VERSION 5.8 ;
BUSBITCHARS "[]" ;
DIVIDERCHAR "/" ;
UNITS
    DATABASE MICRONS 1000 ;
END UNITS

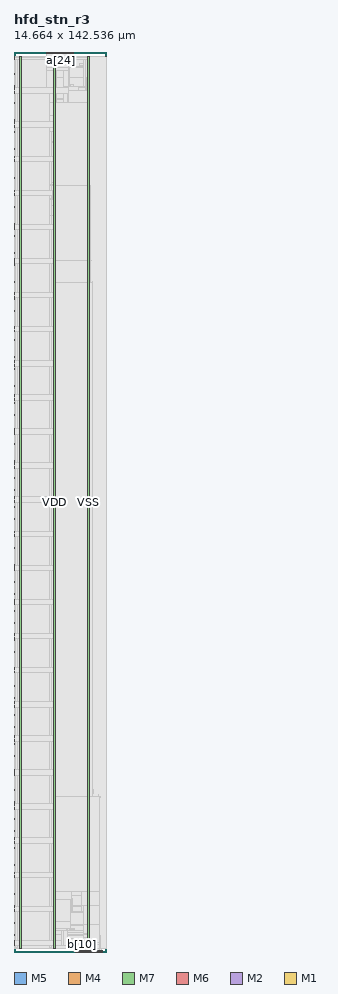
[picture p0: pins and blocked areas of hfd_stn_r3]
MACRO hfd_stn_r3
  FOREIGN hfd_stn_r3 0 0 ;
  CLASS BLOCK ;
  SIZE 14.664 BY 142.536 ;
  PIN a[0]
    DIRECTION INPUT ;
    USE SIGNAL ;
    PORT
      LAYER M5 ;
        RECT  5.184 142.344 5.208 142.536 ;
    END
  END a[0]
  PIN a[10]
    DIRECTION INPUT ;
    USE SIGNAL ;
    PORT
      LAYER M5 ;
        RECT  6.144 142.344 6.168 142.536 ;
    END
  END a[10]
  PIN a[11]
    DIRECTION INPUT ;
    USE SIGNAL ;
    PORT
      LAYER M5 ;
        RECT  6.24 142.344 6.264 142.536 ;
    END
  END a[11]
  PIN a[12]
    DIRECTION INPUT ;
    USE SIGNAL ;
    PORT
      LAYER M5 ;
        RECT  6.336 142.344 6.36 142.536 ;
    END
  END a[12]
  PIN a[13]
    DIRECTION INPUT ;
    USE SIGNAL ;
    PORT
      LAYER M5 ;
        RECT  6.432 142.344 6.456 142.536 ;
    END
  END a[13]
  PIN a[14]
    DIRECTION INPUT ;
    USE SIGNAL ;
    PORT
      LAYER M5 ;
        RECT  6.528 142.344 6.552 142.536 ;
    END
  END a[14]
  PIN a[15]
    DIRECTION INPUT ;
    USE SIGNAL ;
    PORT
      LAYER M5 ;
        RECT  6.624 142.344 6.648 142.536 ;
    END
  END a[15]
  PIN a[16]
    DIRECTION INPUT ;
    USE SIGNAL ;
    PORT
      LAYER M5 ;
        RECT  6.72 142.344 6.744 142.536 ;
    END
  END a[16]
  PIN a[17]
    DIRECTION INPUT ;
    USE SIGNAL ;
    PORT
      LAYER M5 ;
        RECT  6.816 142.344 6.84 142.536 ;
    END
  END a[17]
  PIN a[18]
    DIRECTION INPUT ;
    USE SIGNAL ;
    PORT
      LAYER M5 ;
        RECT  6.912 142.344 6.936 142.536 ;
    END
  END a[18]
  PIN a[19]
    DIRECTION INPUT ;
    USE SIGNAL ;
    PORT
      LAYER M5 ;
        RECT  7.008 142.344 7.032 142.536 ;
    END
  END a[19]
  PIN a[1]
    DIRECTION INPUT ;
    USE SIGNAL ;
    PORT
      LAYER M5 ;
        RECT  5.28 142.344 5.304 142.536 ;
    END
  END a[1]
  PIN a[20]
    DIRECTION INPUT ;
    USE SIGNAL ;
    PORT
      LAYER M5 ;
        RECT  7.104 142.344 7.128 142.536 ;
    END
  END a[20]
  PIN a[21]
    DIRECTION INPUT ;
    USE SIGNAL ;
    PORT
      LAYER M5 ;
        RECT  7.2 142.344 7.224 142.536 ;
    END
  END a[21]
  PIN a[22]
    DIRECTION INPUT ;
    USE SIGNAL ;
    PORT
      LAYER M5 ;
        RECT  7.296 142.344 7.32 142.536 ;
    END
  END a[22]
  PIN a[23]
    DIRECTION INPUT ;
    USE SIGNAL ;
    PORT
      LAYER M5 ;
        RECT  7.392 142.344 7.416 142.536 ;
    END
  END a[23]
  PIN a[24]
    DIRECTION INPUT ;
    USE SIGNAL ;
    PORT
      LAYER M5 ;
        RECT  7.488 142.344 7.512 142.536 ;
    END
  END a[24]
  PIN a[25]
    DIRECTION INPUT ;
    USE SIGNAL ;
    PORT
      LAYER M5 ;
        RECT  7.584 142.344 7.608 142.536 ;
    END
  END a[25]
  PIN a[26]
    DIRECTION INPUT ;
    USE SIGNAL ;
    PORT
      LAYER M5 ;
        RECT  7.68 142.344 7.704 142.536 ;
    END
  END a[26]
  PIN a[27]
    DIRECTION INPUT ;
    USE SIGNAL ;
    PORT
      LAYER M5 ;
        RECT  7.776 142.344 7.8 142.536 ;
    END
  END a[27]
  PIN a[28]
    DIRECTION INPUT ;
    USE SIGNAL ;
    PORT
      LAYER M5 ;
        RECT  7.872 142.344 7.896 142.536 ;
    END
  END a[28]
  PIN a[29]
    DIRECTION INPUT ;
    USE SIGNAL ;
    PORT
      LAYER M5 ;
        RECT  7.968 142.344 7.992 142.536 ;
    END
  END a[29]
  PIN a[2]
    DIRECTION INPUT ;
    USE SIGNAL ;
    PORT
      LAYER M5 ;
        RECT  5.376 142.344 5.4 142.536 ;
    END
  END a[2]
  PIN a[30]
    DIRECTION INPUT ;
    USE SIGNAL ;
    PORT
      LAYER M5 ;
        RECT  8.064 142.344 8.088 142.536 ;
    END
  END a[30]
  PIN a[31]
    DIRECTION INPUT ;
    USE SIGNAL ;
    PORT
      LAYER M5 ;
        RECT  8.16 142.344 8.184 142.536 ;
    END
  END a[31]
  PIN a[32]
    DIRECTION INPUT ;
    USE SIGNAL ;
    PORT
      LAYER M5 ;
        RECT  8.256 142.344 8.28 142.536 ;
    END
  END a[32]
  PIN a[33]
    DIRECTION INPUT ;
    USE SIGNAL ;
    PORT
      LAYER M5 ;
        RECT  8.352 142.344 8.376 142.536 ;
    END
  END a[33]
  PIN a[34]
    DIRECTION INPUT ;
    USE SIGNAL ;
    PORT
      LAYER M5 ;
        RECT  8.448 142.344 8.472 142.536 ;
    END
  END a[34]
  PIN a[35]
    DIRECTION INPUT ;
    USE SIGNAL ;
    PORT
      LAYER M5 ;
        RECT  8.544 142.344 8.568 142.536 ;
    END
  END a[35]
  PIN a[36]
    DIRECTION INPUT ;
    USE SIGNAL ;
    PORT
      LAYER M5 ;
        RECT  8.64 142.344 8.664 142.536 ;
    END
  END a[36]
  PIN a[37]
    DIRECTION INPUT ;
    USE SIGNAL ;
    PORT
      LAYER M5 ;
        RECT  8.736 142.344 8.76 142.536 ;
    END
  END a[37]
  PIN a[38]
    DIRECTION INPUT ;
    USE SIGNAL ;
    PORT
      LAYER M5 ;
        RECT  8.832 142.344 8.856 142.536 ;
    END
  END a[38]
  PIN a[39]
    DIRECTION INPUT ;
    USE SIGNAL ;
    PORT
      LAYER M5 ;
        RECT  8.928 142.344 8.952 142.536 ;
    END
  END a[39]
  PIN a[3]
    DIRECTION INPUT ;
    USE SIGNAL ;
    PORT
      LAYER M5 ;
        RECT  5.472 142.344 5.496 142.536 ;
    END
  END a[3]
  PIN a[40]
    DIRECTION INPUT ;
    USE SIGNAL ;
    PORT
      LAYER M5 ;
        RECT  9.024 142.344 9.048 142.536 ;
    END
  END a[40]
  PIN a[41]
    DIRECTION INPUT ;
    USE SIGNAL ;
    PORT
      LAYER M5 ;
        RECT  9.12 142.344 9.144 142.536 ;
    END
  END a[41]
  PIN a[42]
    DIRECTION INPUT ;
    USE SIGNAL ;
    PORT
      LAYER M5 ;
        RECT  9.216 142.344 9.24 142.536 ;
    END
  END a[42]
  PIN a[43]
    DIRECTION INPUT ;
    USE SIGNAL ;
    PORT
      LAYER M5 ;
        RECT  9.312 142.344 9.336 142.536 ;
    END
  END a[43]
  PIN a[44]
    DIRECTION INPUT ;
    USE SIGNAL ;
    PORT
      LAYER M5 ;
        RECT  9.408 142.344 9.432 142.536 ;
    END
  END a[44]
  PIN a[4]
    DIRECTION INPUT ;
    USE SIGNAL ;
    PORT
      LAYER M5 ;
        RECT  5.568 142.344 5.592 142.536 ;
    END
  END a[4]
  PIN a[5]
    DIRECTION INPUT ;
    USE SIGNAL ;
    PORT
      LAYER M5 ;
        RECT  5.664 142.344 5.688 142.536 ;
    END
  END a[5]
  PIN a[6]
    DIRECTION INPUT ;
    USE SIGNAL ;
    PORT
      LAYER M5 ;
        RECT  5.76 142.344 5.784 142.536 ;
    END
  END a[6]
  PIN a[7]
    DIRECTION INPUT ;
    USE SIGNAL ;
    PORT
      LAYER M5 ;
        RECT  5.856 142.344 5.88 142.536 ;
    END
  END a[7]
  PIN a[8]
    DIRECTION INPUT ;
    USE SIGNAL ;
    PORT
      LAYER M5 ;
        RECT  5.952 142.344 5.976 142.536 ;
    END
  END a[8]
  PIN a[9]
    DIRECTION INPUT ;
    USE SIGNAL ;
    PORT
      LAYER M5 ;
        RECT  6.048 142.344 6.072 142.536 ;
    END
  END a[9]
  PIN b[0]
    DIRECTION OUTPUT ;
    USE SIGNAL ;
    PORT
      LAYER M5 ;
        RECT  9.744 0 9.768 0.192 ;
    END
  END b[0]
  PIN b[10]
    DIRECTION OUTPUT ;
    USE SIGNAL ;
    PORT
      LAYER M5 ;
        RECT  10.704 0 10.728 0.192 ;
    END
  END b[10]
  PIN b[11]
    DIRECTION OUTPUT ;
    USE SIGNAL ;
    PORT
      LAYER M5 ;
        RECT  10.8 0 10.824 0.192 ;
    END
  END b[11]
  PIN b[12]
    DIRECTION OUTPUT ;
    USE SIGNAL ;
    PORT
      LAYER M5 ;
        RECT  10.896 0 10.92 0.192 ;
    END
  END b[12]
  PIN b[13]
    DIRECTION OUTPUT ;
    USE SIGNAL ;
    PORT
      LAYER M5 ;
        RECT  10.992 0 11.016 0.192 ;
    END
  END b[13]
  PIN b[14]
    DIRECTION OUTPUT ;
    USE SIGNAL ;
    PORT
      LAYER M5 ;
        RECT  11.088 0 11.112 0.192 ;
    END
  END b[14]
  PIN b[15]
    DIRECTION OUTPUT ;
    USE SIGNAL ;
    PORT
      LAYER M5 ;
        RECT  11.184 0 11.208 0.192 ;
    END
  END b[15]
  PIN b[16]
    DIRECTION OUTPUT ;
    USE SIGNAL ;
    PORT
      LAYER M5 ;
        RECT  11.28 0 11.304 0.192 ;
    END
  END b[16]
  PIN b[17]
    DIRECTION OUTPUT ;
    USE SIGNAL ;
    PORT
      LAYER M5 ;
        RECT  11.376 0 11.4 0.192 ;
    END
  END b[17]
  PIN b[18]
    DIRECTION OUTPUT ;
    USE SIGNAL ;
    PORT
      LAYER M5 ;
        RECT  11.472 0 11.496 0.192 ;
    END
  END b[18]
  PIN b[19]
    DIRECTION OUTPUT ;
    USE SIGNAL ;
    PORT
      LAYER M5 ;
        RECT  11.568 0 11.592 0.192 ;
    END
  END b[19]
  PIN b[1]
    DIRECTION OUTPUT ;
    USE SIGNAL ;
    PORT
      LAYER M5 ;
        RECT  9.84 0 9.864 0.192 ;
    END
  END b[1]
  PIN b[20]
    DIRECTION OUTPUT ;
    USE SIGNAL ;
    PORT
      LAYER M5 ;
        RECT  11.664 0 11.688 0.192 ;
    END
  END b[20]
  PIN b[21]
    DIRECTION OUTPUT ;
    USE SIGNAL ;
    PORT
      LAYER M5 ;
        RECT  11.76 0 11.784 0.192 ;
    END
  END b[21]
  PIN b[22]
    DIRECTION OUTPUT ;
    USE SIGNAL ;
    PORT
      LAYER M5 ;
        RECT  11.856 0 11.88 0.192 ;
    END
  END b[22]
  PIN b[23]
    DIRECTION OUTPUT ;
    USE SIGNAL ;
    PORT
      LAYER M5 ;
        RECT  11.952 0 11.976 0.192 ;
    END
  END b[23]
  PIN b[24]
    DIRECTION OUTPUT ;
    USE SIGNAL ;
    PORT
      LAYER M5 ;
        RECT  12.048 0 12.072 0.192 ;
    END
  END b[24]
  PIN b[25]
    DIRECTION OUTPUT ;
    USE SIGNAL ;
    PORT
      LAYER M5 ;
        RECT  12.144 0 12.168 0.192 ;
    END
  END b[25]
  PIN b[26]
    DIRECTION OUTPUT ;
    USE SIGNAL ;
    PORT
      LAYER M5 ;
        RECT  12.24 0 12.264 0.192 ;
    END
  END b[26]
  PIN b[27]
    DIRECTION OUTPUT ;
    USE SIGNAL ;
    PORT
      LAYER M5 ;
        RECT  12.336 0 12.36 0.192 ;
    END
  END b[27]
  PIN b[28]
    DIRECTION OUTPUT ;
    USE SIGNAL ;
    PORT
      LAYER M5 ;
        RECT  12.432 0 12.456 0.192 ;
    END
  END b[28]
  PIN b[29]
    DIRECTION OUTPUT ;
    USE SIGNAL ;
    PORT
      LAYER M5 ;
        RECT  12.528 0 12.552 0.192 ;
    END
  END b[29]
  PIN b[2]
    DIRECTION OUTPUT ;
    USE SIGNAL ;
    PORT
      LAYER M5 ;
        RECT  9.936 0 9.96 0.192 ;
    END
  END b[2]
  PIN b[30]
    DIRECTION OUTPUT ;
    USE SIGNAL ;
    PORT
      LAYER M5 ;
        RECT  12.624 0 12.648 0.192 ;
    END
  END b[30]
  PIN b[31]
    DIRECTION OUTPUT ;
    USE SIGNAL ;
    PORT
      LAYER M5 ;
        RECT  12.72 0 12.744 0.192 ;
    END
  END b[31]
  PIN b[32]
    DIRECTION OUTPUT ;
    USE SIGNAL ;
    PORT
      LAYER M5 ;
        RECT  12.816 0 12.84 0.192 ;
    END
  END b[32]
  PIN b[33]
    DIRECTION OUTPUT ;
    USE SIGNAL ;
    PORT
      LAYER M5 ;
        RECT  12.912 0 12.936 0.192 ;
    END
  END b[33]
  PIN b[34]
    DIRECTION OUTPUT ;
    USE SIGNAL ;
    PORT
      LAYER M5 ;
        RECT  13.008 0 13.032 0.192 ;
    END
  END b[34]
  PIN b[35]
    DIRECTION OUTPUT ;
    USE SIGNAL ;
    PORT
      LAYER M5 ;
        RECT  13.104 0 13.128 0.192 ;
    END
  END b[35]
  PIN b[36]
    DIRECTION OUTPUT ;
    USE SIGNAL ;
    PORT
      LAYER M5 ;
        RECT  13.2 0 13.224 0.192 ;
    END
  END b[36]
  PIN b[37]
    DIRECTION OUTPUT ;
    USE SIGNAL ;
    PORT
      LAYER M5 ;
        RECT  13.296 0 13.32 0.192 ;
    END
  END b[37]
  PIN b[38]
    DIRECTION OUTPUT ;
    USE SIGNAL ;
    PORT
      LAYER M5 ;
        RECT  13.392 0 13.416 0.192 ;
    END
  END b[38]
  PIN b[39]
    DIRECTION OUTPUT ;
    USE SIGNAL ;
    PORT
      LAYER M5 ;
        RECT  13.488 0 13.512 0.192 ;
    END
  END b[39]
  PIN b[3]
    DIRECTION OUTPUT ;
    USE SIGNAL ;
    PORT
      LAYER M5 ;
        RECT  10.032 0 10.056 0.192 ;
    END
  END b[3]
  PIN b[40]
    DIRECTION OUTPUT ;
    USE SIGNAL ;
    PORT
      LAYER M5 ;
        RECT  13.584 0 13.608 0.192 ;
    END
  END b[40]
  PIN b[41]
    DIRECTION OUTPUT ;
    USE SIGNAL ;
    PORT
      LAYER M5 ;
        RECT  13.68 0 13.704 0.192 ;
    END
  END b[41]
  PIN b[42]
    DIRECTION OUTPUT ;
    USE SIGNAL ;
    PORT
      LAYER M5 ;
        RECT  13.776 0 13.8 0.192 ;
    END
  END b[42]
  PIN b[43]
    DIRECTION OUTPUT ;
    USE SIGNAL ;
    PORT
      LAYER M5 ;
        RECT  13.872 0 13.896 0.192 ;
    END
  END b[43]
  PIN b[44]
    DIRECTION OUTPUT ;
    USE SIGNAL ;
    PORT
      LAYER M5 ;
        RECT  13.968 0 13.992 0.192 ;
    END
  END b[44]
  PIN b[4]
    DIRECTION OUTPUT ;
    USE SIGNAL ;
    PORT
      LAYER M5 ;
        RECT  10.128 0 10.152 0.192 ;
    END
  END b[4]
  PIN b[5]
    DIRECTION OUTPUT ;
    USE SIGNAL ;
    PORT
      LAYER M5 ;
        RECT  10.224 0 10.248 0.192 ;
    END
  END b[5]
  PIN b[6]
    DIRECTION OUTPUT ;
    USE SIGNAL ;
    PORT
      LAYER M5 ;
        RECT  10.32 0 10.344 0.192 ;
    END
  END b[6]
  PIN b[7]
    DIRECTION OUTPUT ;
    USE SIGNAL ;
    PORT
      LAYER M5 ;
        RECT  10.416 0 10.44 0.192 ;
    END
  END b[7]
  PIN b[8]
    DIRECTION OUTPUT ;
    USE SIGNAL ;
    PORT
      LAYER M5 ;
        RECT  10.512 0 10.536 0.192 ;
    END
  END b[8]
  PIN b[9]
    DIRECTION OUTPUT ;
    USE SIGNAL ;
    PORT
      LAYER M5 ;
        RECT  10.608 0 10.632 0.192 ;
    END
  END b[9]
  PIN rst[0]
    DIRECTION INPUT ;
    USE SIGNAL ;
    PORT
      LAYER M4 ;
        RECT  14.472 141.84 14.664 141.864 ;
    END
  END rst[0]
  PIN VDD
    DIRECTION INOUT ;
    USE POWER ;
    PORT
      LAYER M7 ;
        RECT  6.256 0.531 6.544 141.759 ;
      LAYER M6 ;
        RECT  0 136.572 0.032 136.86 ;
        RECT  0 131.172 0.032 131.46 ;
        RECT  0 125.772 0.032 126.06 ;
        RECT  0 120.372 0.032 120.66 ;
        RECT  0 114.972 0.032 115.26 ;
        RECT  0 109.572 0.032 109.86 ;
        RECT  0 104.172 0.032 104.46 ;
        RECT  0 98.772 0.032 99.06 ;
        RECT  0 93.372 0.032 93.66 ;
        RECT  0 87.972 0.032 88.26 ;
        RECT  0 82.572 0.032 82.86 ;
        RECT  0 77.172 0.032 77.46 ;
        RECT  0 71.772 0.032 72.06 ;
        RECT  0 66.372 0.032 66.66 ;
        RECT  0 60.972 0.032 61.26 ;
        RECT  0 55.572 0.032 55.86 ;
        RECT  0 50.172 0.032 50.46 ;
        RECT  0 44.772 0.032 45.06 ;
        RECT  0 39.372 0.032 39.66 ;
        RECT  0 33.972 0.032 34.26 ;
        RECT  0 28.572 0.032 28.86 ;
        RECT  0 23.172 0.032 23.46 ;
        RECT  0 17.772 0.032 18.06 ;
        RECT  0 12.372 0.032 12.66 ;
        RECT  0 6.972 0.032 7.26 ;
        RECT  0 1.572 0.032 1.86 ;
      LAYER M2 ;
        RECT  0 141.741 0.018 141.759 ;
        RECT  0 141.201 0.018 141.219 ;
        RECT  0 140.661 0.018 140.679 ;
        RECT  0 140.121 0.018 140.139 ;
        RECT  0 139.581 0.018 139.599 ;
        RECT  0 139.041 0.018 139.059 ;
        RECT  0 138.501 0.018 138.519 ;
        RECT  0 137.961 0.018 137.979 ;
        RECT  0 137.421 0.018 137.439 ;
        RECT  0 136.881 0.018 136.899 ;
        RECT  0 136.341 0.018 136.359 ;
        RECT  0 135.801 0.018 135.819 ;
        RECT  0 135.261 0.018 135.279 ;
        RECT  0 134.721 0.018 134.739 ;
        RECT  0 134.181 0.018 134.199 ;
        RECT  0 133.641 0.018 133.659 ;
        RECT  0 133.101 0.018 133.119 ;
        RECT  0 132.561 0.018 132.579 ;
        RECT  0 132.021 0.018 132.039 ;
        RECT  0 131.481 0.018 131.499 ;
        RECT  0 130.941 0.018 130.959 ;
        RECT  0 130.401 0.018 130.419 ;
        RECT  0 129.861 0.018 129.879 ;
        RECT  0 129.321 0.018 129.339 ;
        RECT  0 128.781 0.018 128.799 ;
        RECT  0 128.241 0.018 128.259 ;
        RECT  0 127.701 0.018 127.719 ;
        RECT  0 127.161 0.018 127.179 ;
        RECT  0 126.621 0.018 126.639 ;
        RECT  0 126.081 0.018 126.099 ;
        RECT  0 125.541 0.018 125.559 ;
        RECT  0 125.001 0.018 125.019 ;
        RECT  0 124.461 0.018 124.479 ;
        RECT  0 123.921 0.018 123.939 ;
        RECT  0 123.381 0.018 123.399 ;
        RECT  0 122.841 0.018 122.859 ;
        RECT  0 122.301 0.018 122.319 ;
        RECT  0 121.761 0.018 121.779 ;
        RECT  0 121.221 0.018 121.239 ;
        RECT  0 120.681 0.018 120.699 ;
        RECT  0 120.141 0.018 120.159 ;
        RECT  0 119.601 0.018 119.619 ;
        RECT  0 119.061 0.018 119.079 ;
        RECT  0 118.521 0.018 118.539 ;
        RECT  0 117.981 0.018 117.999 ;
        RECT  0 117.441 0.018 117.459 ;
        RECT  0 116.901 0.018 116.919 ;
        RECT  0 116.361 0.018 116.379 ;
        RECT  0 115.821 0.018 115.839 ;
        RECT  0 115.281 0.018 115.299 ;
        RECT  0 114.741 0.018 114.759 ;
        RECT  0 114.201 0.018 114.219 ;
        RECT  0 113.661 0.018 113.679 ;
        RECT  0 113.121 0.018 113.139 ;
        RECT  0 112.581 0.018 112.599 ;
        RECT  0 112.041 0.018 112.059 ;
        RECT  0 111.501 0.018 111.519 ;
        RECT  0 110.961 0.018 110.979 ;
        RECT  0 110.421 0.018 110.439 ;
        RECT  0 109.881 0.018 109.899 ;
        RECT  0 109.341 0.018 109.359 ;
        RECT  0 108.801 0.018 108.819 ;
        RECT  0 108.261 0.018 108.279 ;
        RECT  0 107.721 0.018 107.739 ;
        RECT  0 107.181 0.018 107.199 ;
        RECT  0 106.641 0.018 106.659 ;
        RECT  0 106.101 0.018 106.119 ;
        RECT  0 105.561 0.018 105.579 ;
        RECT  0 105.021 0.018 105.039 ;
        RECT  0 104.481 0.018 104.499 ;
        RECT  0 103.941 0.018 103.959 ;
        RECT  0 103.401 0.018 103.419 ;
        RECT  0 102.861 0.018 102.879 ;
        RECT  0 102.321 0.018 102.339 ;
        RECT  0 101.781 0.018 101.799 ;
        RECT  0 101.241 0.018 101.259 ;
        RECT  0 100.701 0.018 100.719 ;
        RECT  0 100.161 0.018 100.179 ;
        RECT  0 99.621 0.018 99.639 ;
        RECT  0 99.081 0.018 99.099 ;
        RECT  0 98.541 0.018 98.559 ;
        RECT  0 98.001 0.018 98.019 ;
        RECT  0 97.461 0.018 97.479 ;
        RECT  0 96.921 0.018 96.939 ;
        RECT  0 96.381 0.018 96.399 ;
        RECT  0 95.841 0.018 95.859 ;
        RECT  0 95.301 0.018 95.319 ;
        RECT  0 94.761 0.018 94.779 ;
        RECT  0 94.221 0.018 94.239 ;
        RECT  0 93.681 0.018 93.699 ;
        RECT  0 93.141 0.018 93.159 ;
        RECT  0 92.601 0.018 92.619 ;
        RECT  0 92.061 0.018 92.079 ;
        RECT  0 91.521 0.018 91.539 ;
        RECT  0 90.981 0.018 90.999 ;
        RECT  0 90.441 0.018 90.459 ;
        RECT  0 89.901 0.018 89.919 ;
        RECT  0 89.361 0.018 89.379 ;
        RECT  0 88.821 0.018 88.839 ;
        RECT  0 88.281 0.018 88.299 ;
        RECT  0 87.741 0.018 87.759 ;
        RECT  0 87.201 0.018 87.219 ;
        RECT  0 86.661 0.018 86.679 ;
        RECT  0 86.121 0.018 86.139 ;
        RECT  0 85.581 0.018 85.599 ;
        RECT  0 85.041 0.018 85.059 ;
        RECT  0 84.501 0.018 84.519 ;
        RECT  0 83.961 0.018 83.979 ;
        RECT  0 83.421 0.018 83.439 ;
        RECT  0 82.881 0.018 82.899 ;
        RECT  0 82.341 0.018 82.359 ;
        RECT  0 81.801 0.018 81.819 ;
        RECT  0 81.261 0.018 81.279 ;
        RECT  0 80.721 0.018 80.739 ;
        RECT  0 80.181 0.018 80.199 ;
        RECT  0 79.641 0.018 79.659 ;
        RECT  0 79.101 0.018 79.119 ;
        RECT  0 78.561 0.018 78.579 ;
        RECT  0 78.021 0.018 78.039 ;
        RECT  0 77.481 0.018 77.499 ;
        RECT  0 76.941 0.018 76.959 ;
        RECT  0 76.401 0.018 76.419 ;
        RECT  0 75.861 0.018 75.879 ;
        RECT  0 75.321 0.018 75.339 ;
        RECT  0 74.781 0.018 74.799 ;
        RECT  0 74.241 0.018 74.259 ;
        RECT  0 73.701 0.018 73.719 ;
        RECT  0 73.161 0.018 73.179 ;
        RECT  0 72.621 0.018 72.639 ;
        RECT  0 72.081 0.018 72.099 ;
        RECT  0 71.541 0.018 71.559 ;
        RECT  0 71.001 0.018 71.019 ;
        RECT  0 70.461 0.018 70.479 ;
        RECT  0 69.921 0.018 69.939 ;
        RECT  0 69.381 0.018 69.399 ;
        RECT  0 68.841 0.018 68.859 ;
        RECT  0 68.301 0.018 68.319 ;
        RECT  0 67.761 0.018 67.779 ;
        RECT  0 67.221 0.018 67.239 ;
        RECT  0 66.681 0.018 66.699 ;
        RECT  0 66.141 0.018 66.159 ;
        RECT  0 65.601 0.018 65.619 ;
        RECT  0 65.061 0.018 65.079 ;
        RECT  0 64.521 0.018 64.539 ;
        RECT  0 63.981 0.018 63.999 ;
        RECT  0 63.441 0.018 63.459 ;
        RECT  0 62.901 0.018 62.919 ;
        RECT  0 62.361 0.018 62.379 ;
        RECT  0 61.821 0.018 61.839 ;
        RECT  0 61.281 0.018 61.299 ;
        RECT  0 60.741 0.018 60.759 ;
        RECT  0 60.201 0.018 60.219 ;
        RECT  0 59.661 0.018 59.679 ;
        RECT  0 59.121 0.018 59.139 ;
        RECT  0 58.581 0.018 58.599 ;
        RECT  0 58.041 0.018 58.059 ;
        RECT  0 57.501 0.018 57.519 ;
        RECT  0 56.961 0.018 56.979 ;
        RECT  0 56.421 0.018 56.439 ;
        RECT  0 55.881 0.018 55.899 ;
        RECT  0 55.341 0.018 55.359 ;
        RECT  0 54.801 0.018 54.819 ;
        RECT  0 54.261 0.018 54.279 ;
        RECT  0 53.721 0.018 53.739 ;
        RECT  0 53.181 0.018 53.199 ;
        RECT  0 52.641 0.018 52.659 ;
        RECT  0 52.101 0.018 52.119 ;
        RECT  0 51.561 0.018 51.579 ;
        RECT  0 51.021 0.018 51.039 ;
        RECT  0 50.481 0.018 50.499 ;
        RECT  0 49.941 0.018 49.959 ;
        RECT  0 49.401 0.018 49.419 ;
        RECT  0 48.861 0.018 48.879 ;
        RECT  0 48.321 0.018 48.339 ;
        RECT  0 47.781 0.018 47.799 ;
        RECT  0 47.241 0.018 47.259 ;
        RECT  0 46.701 0.018 46.719 ;
        RECT  0 46.161 0.018 46.179 ;
        RECT  0 45.621 0.018 45.639 ;
        RECT  0 45.081 0.018 45.099 ;
        RECT  0 44.541 0.018 44.559 ;
        RECT  0 44.001 0.018 44.019 ;
        RECT  0 43.461 0.018 43.479 ;
        RECT  0 42.921 0.018 42.939 ;
        RECT  0 42.381 0.018 42.399 ;
        RECT  0 41.841 0.018 41.859 ;
        RECT  0 41.301 0.018 41.319 ;
        RECT  0 40.761 0.018 40.779 ;
        RECT  0 40.221 0.018 40.239 ;
        RECT  0 39.681 0.018 39.699 ;
        RECT  0 39.141 0.018 39.159 ;
        RECT  0 38.601 0.018 38.619 ;
        RECT  0 38.061 0.018 38.079 ;
        RECT  0 37.521 0.018 37.539 ;
        RECT  0 36.981 0.018 36.999 ;
        RECT  0 36.441 0.018 36.459 ;
        RECT  0 35.901 0.018 35.919 ;
        RECT  0 35.361 0.018 35.379 ;
        RECT  0 34.821 0.018 34.839 ;
        RECT  0 34.281 0.018 34.299 ;
        RECT  0 33.741 0.018 33.759 ;
        RECT  0 33.201 0.018 33.219 ;
        RECT  0 32.661 0.018 32.679 ;
        RECT  0 32.121 0.018 32.139 ;
        RECT  0 31.581 0.018 31.599 ;
        RECT  0 31.041 0.018 31.059 ;
        RECT  0 30.501 0.018 30.519 ;
        RECT  0 29.961 0.018 29.979 ;
        RECT  0 29.421 0.018 29.439 ;
        RECT  0 28.881 0.018 28.899 ;
        RECT  0 28.341 0.018 28.359 ;
        RECT  0 27.801 0.018 27.819 ;
        RECT  0 27.261 0.018 27.279 ;
        RECT  0 26.721 0.018 26.739 ;
        RECT  0 26.181 0.018 26.199 ;
        RECT  0 25.641 0.018 25.659 ;
        RECT  0 25.101 0.018 25.119 ;
        RECT  0 24.561 0.018 24.579 ;
        RECT  0 24.021 0.018 24.039 ;
        RECT  0 23.481 0.018 23.499 ;
        RECT  0 22.941 0.018 22.959 ;
        RECT  0 22.401 0.018 22.419 ;
        RECT  0 21.861 0.018 21.879 ;
        RECT  0 21.321 0.018 21.339 ;
        RECT  0 20.781 0.018 20.799 ;
        RECT  0 20.241 0.018 20.259 ;
        RECT  0 19.701 0.018 19.719 ;
        RECT  0 19.161 0.018 19.179 ;
        RECT  0 18.621 0.018 18.639 ;
        RECT  0 18.081 0.018 18.099 ;
        RECT  0 17.541 0.018 17.559 ;
        RECT  0 17.001 0.018 17.019 ;
        RECT  0 16.461 0.018 16.479 ;
        RECT  0 15.921 0.018 15.939 ;
        RECT  0 15.381 0.018 15.399 ;
        RECT  0 14.841 0.018 14.859 ;
        RECT  0 14.301 0.018 14.319 ;
        RECT  0 13.761 0.018 13.779 ;
        RECT  0 13.221 0.018 13.239 ;
        RECT  0 12.681 0.018 12.699 ;
        RECT  0 12.141 0.018 12.159 ;
        RECT  0 11.601 0.018 11.619 ;
        RECT  0 11.061 0.018 11.079 ;
        RECT  0 10.521 0.018 10.539 ;
        RECT  0 9.981 0.018 9.999 ;
        RECT  0 9.441 0.018 9.459 ;
        RECT  0 8.901 0.018 8.919 ;
        RECT  0 8.361 0.018 8.379 ;
        RECT  0 7.821 0.018 7.839 ;
        RECT  0 7.281 0.018 7.299 ;
        RECT  0 6.741 0.018 6.759 ;
        RECT  0 6.201 0.018 6.219 ;
        RECT  0 5.661 0.018 5.679 ;
        RECT  0 5.121 0.018 5.139 ;
        RECT  0 4.581 0.018 4.599 ;
        RECT  0 4.041 0.018 4.059 ;
        RECT  0 3.501 0.018 3.519 ;
        RECT  0 2.961 0.018 2.979 ;
        RECT  0 2.421 0.018 2.439 ;
        RECT  0 1.881 0.018 1.899 ;
        RECT  0 1.341 0.018 1.359 ;
        RECT  0 0.801 0.018 0.819 ;
      LAYER M1 ;
        RECT  0 141.741 0.018 141.759 ;
        RECT  0 141.201 0.018 141.219 ;
        RECT  0 140.661 0.018 140.679 ;
        RECT  0 140.121 0.018 140.139 ;
        RECT  0 139.581 0.018 139.599 ;
        RECT  0 139.041 0.018 139.059 ;
        RECT  0 138.501 0.018 138.519 ;
        RECT  0 137.961 0.018 137.979 ;
        RECT  0 137.421 0.018 137.439 ;
        RECT  0 136.881 0.018 136.899 ;
        RECT  0 136.341 0.018 136.359 ;
        RECT  0 135.801 0.018 135.819 ;
        RECT  0 135.261 0.018 135.279 ;
        RECT  0 134.721 0.018 134.739 ;
        RECT  0 134.181 0.018 134.199 ;
        RECT  0 133.641 0.018 133.659 ;
        RECT  0 133.101 0.018 133.119 ;
        RECT  0 132.561 0.018 132.579 ;
        RECT  0 132.021 0.018 132.039 ;
        RECT  0 131.481 0.018 131.499 ;
        RECT  0 130.941 0.018 130.959 ;
        RECT  0 130.401 0.018 130.419 ;
        RECT  0 129.861 0.018 129.879 ;
        RECT  0 129.321 0.018 129.339 ;
        RECT  0 128.781 0.018 128.799 ;
        RECT  0 128.241 0.018 128.259 ;
        RECT  0 127.701 0.018 127.719 ;
        RECT  0 127.161 0.018 127.179 ;
        RECT  0 126.621 0.018 126.639 ;
        RECT  0 126.081 0.018 126.099 ;
        RECT  0 125.541 0.018 125.559 ;
        RECT  0 125.001 0.018 125.019 ;
        RECT  0 124.461 0.018 124.479 ;
        RECT  0 123.921 0.018 123.939 ;
        RECT  0 123.381 0.018 123.399 ;
        RECT  0 122.841 0.018 122.859 ;
        RECT  0 122.301 0.018 122.319 ;
        RECT  0 121.761 0.018 121.779 ;
        RECT  0 121.221 0.018 121.239 ;
        RECT  0 120.681 0.018 120.699 ;
        RECT  0 120.141 0.018 120.159 ;
        RECT  0 119.601 0.018 119.619 ;
        RECT  0 119.061 0.018 119.079 ;
        RECT  0 118.521 0.018 118.539 ;
        RECT  0 117.981 0.018 117.999 ;
        RECT  0 117.441 0.018 117.459 ;
        RECT  0 116.901 0.018 116.919 ;
        RECT  0 116.361 0.018 116.379 ;
        RECT  0 115.821 0.018 115.839 ;
        RECT  0 115.281 0.018 115.299 ;
        RECT  0 114.741 0.018 114.759 ;
        RECT  0 114.201 0.018 114.219 ;
        RECT  0 113.661 0.018 113.679 ;
        RECT  0 113.121 0.018 113.139 ;
        RECT  0 112.581 0.018 112.599 ;
        RECT  0 112.041 0.018 112.059 ;
        RECT  0 111.501 0.018 111.519 ;
        RECT  0 110.961 0.018 110.979 ;
        RECT  0 110.421 0.018 110.439 ;
        RECT  0 109.881 0.018 109.899 ;
        RECT  0 109.341 0.018 109.359 ;
        RECT  0 108.801 0.018 108.819 ;
        RECT  0 108.261 0.018 108.279 ;
        RECT  0 107.721 0.018 107.739 ;
        RECT  0 107.181 0.018 107.199 ;
        RECT  0 106.641 0.018 106.659 ;
        RECT  0 106.101 0.018 106.119 ;
        RECT  0 105.561 0.018 105.579 ;
        RECT  0 105.021 0.018 105.039 ;
        RECT  0 104.481 0.018 104.499 ;
        RECT  0 103.941 0.018 103.959 ;
        RECT  0 103.401 0.018 103.419 ;
        RECT  0 102.861 0.018 102.879 ;
        RECT  0 102.321 0.018 102.339 ;
        RECT  0 101.781 0.018 101.799 ;
        RECT  0 101.241 0.018 101.259 ;
        RECT  0 100.701 0.018 100.719 ;
        RECT  0 100.161 0.018 100.179 ;
        RECT  0 99.621 0.018 99.639 ;
        RECT  0 99.081 0.018 99.099 ;
        RECT  0 98.541 0.018 98.559 ;
        RECT  0 98.001 0.018 98.019 ;
        RECT  0 97.461 0.018 97.479 ;
        RECT  0 96.921 0.018 96.939 ;
        RECT  0 96.381 0.018 96.399 ;
        RECT  0 95.841 0.018 95.859 ;
        RECT  0 95.301 0.018 95.319 ;
        RECT  0 94.761 0.018 94.779 ;
        RECT  0 94.221 0.018 94.239 ;
        RECT  0 93.681 0.018 93.699 ;
        RECT  0 93.141 0.018 93.159 ;
        RECT  0 92.601 0.018 92.619 ;
        RECT  0 92.061 0.018 92.079 ;
        RECT  0 91.521 0.018 91.539 ;
        RECT  0 90.981 0.018 90.999 ;
        RECT  0 90.441 0.018 90.459 ;
        RECT  0 89.901 0.018 89.919 ;
        RECT  0 89.361 0.018 89.379 ;
        RECT  0 88.821 0.018 88.839 ;
        RECT  0 88.281 0.018 88.299 ;
        RECT  0 87.741 0.018 87.759 ;
        RECT  0 87.201 0.018 87.219 ;
        RECT  0 86.661 0.018 86.679 ;
        RECT  0 86.121 0.018 86.139 ;
        RECT  0 85.581 0.018 85.599 ;
        RECT  0 85.041 0.018 85.059 ;
        RECT  0 84.501 0.018 84.519 ;
        RECT  0 83.961 0.018 83.979 ;
        RECT  0 83.421 0.018 83.439 ;
        RECT  0 82.881 0.018 82.899 ;
        RECT  0 82.341 0.018 82.359 ;
        RECT  0 81.801 0.018 81.819 ;
        RECT  0 81.261 0.018 81.279 ;
        RECT  0 80.721 0.018 80.739 ;
        RECT  0 80.181 0.018 80.199 ;
        RECT  0 79.641 0.018 79.659 ;
        RECT  0 79.101 0.018 79.119 ;
        RECT  0 78.561 0.018 78.579 ;
        RECT  0 78.021 0.018 78.039 ;
        RECT  0 77.481 0.018 77.499 ;
        RECT  0 76.941 0.018 76.959 ;
        RECT  0 76.401 0.018 76.419 ;
        RECT  0 75.861 0.018 75.879 ;
        RECT  0 75.321 0.018 75.339 ;
        RECT  0 74.781 0.018 74.799 ;
        RECT  0 74.241 0.018 74.259 ;
        RECT  0 73.701 0.018 73.719 ;
        RECT  0 73.161 0.018 73.179 ;
        RECT  0 72.621 0.018 72.639 ;
        RECT  0 72.081 0.018 72.099 ;
        RECT  0 71.541 0.018 71.559 ;
        RECT  0 71.001 0.018 71.019 ;
        RECT  0 70.461 0.018 70.479 ;
        RECT  0 69.921 0.018 69.939 ;
        RECT  0 69.381 0.018 69.399 ;
        RECT  0 68.841 0.018 68.859 ;
        RECT  0 68.301 0.018 68.319 ;
        RECT  0 67.761 0.018 67.779 ;
        RECT  0 67.221 0.018 67.239 ;
        RECT  0 66.681 0.018 66.699 ;
        RECT  0 66.141 0.018 66.159 ;
        RECT  0 65.601 0.018 65.619 ;
        RECT  0 65.061 0.018 65.079 ;
        RECT  0 64.521 0.018 64.539 ;
        RECT  0 63.981 0.018 63.999 ;
        RECT  0 63.441 0.018 63.459 ;
        RECT  0 62.901 0.018 62.919 ;
        RECT  0 62.361 0.018 62.379 ;
        RECT  0 61.821 0.018 61.839 ;
        RECT  0 61.281 0.018 61.299 ;
        RECT  0 60.741 0.018 60.759 ;
        RECT  0 60.201 0.018 60.219 ;
        RECT  0 59.661 0.018 59.679 ;
        RECT  0 59.121 0.018 59.139 ;
        RECT  0 58.581 0.018 58.599 ;
        RECT  0 58.041 0.018 58.059 ;
        RECT  0 57.501 0.018 57.519 ;
        RECT  0 56.961 0.018 56.979 ;
        RECT  0 56.421 0.018 56.439 ;
        RECT  0 55.881 0.018 55.899 ;
        RECT  0 55.341 0.018 55.359 ;
        RECT  0 54.801 0.018 54.819 ;
        RECT  0 54.261 0.018 54.279 ;
        RECT  0 53.721 0.018 53.739 ;
        RECT  0 53.181 0.018 53.199 ;
        RECT  0 52.641 0.018 52.659 ;
        RECT  0 52.101 0.018 52.119 ;
        RECT  0 51.561 0.018 51.579 ;
        RECT  0 51.021 0.018 51.039 ;
        RECT  0 50.481 0.018 50.499 ;
        RECT  0 49.941 0.018 49.959 ;
        RECT  0 49.401 0.018 49.419 ;
        RECT  0 48.861 0.018 48.879 ;
        RECT  0 48.321 0.018 48.339 ;
        RECT  0 47.781 0.018 47.799 ;
        RECT  0 47.241 0.018 47.259 ;
        RECT  0 46.701 0.018 46.719 ;
        RECT  0 46.161 0.018 46.179 ;
        RECT  0 45.621 0.018 45.639 ;
        RECT  0 45.081 0.018 45.099 ;
        RECT  0 44.541 0.018 44.559 ;
        RECT  0 44.001 0.018 44.019 ;
        RECT  0 43.461 0.018 43.479 ;
        RECT  0 42.921 0.018 42.939 ;
        RECT  0 42.381 0.018 42.399 ;
        RECT  0 41.841 0.018 41.859 ;
        RECT  0 41.301 0.018 41.319 ;
        RECT  0 40.761 0.018 40.779 ;
        RECT  0 40.221 0.018 40.239 ;
        RECT  0 39.681 0.018 39.699 ;
        RECT  0 39.141 0.018 39.159 ;
        RECT  0 38.601 0.018 38.619 ;
        RECT  0 38.061 0.018 38.079 ;
        RECT  0 37.521 0.018 37.539 ;
        RECT  0 36.981 0.018 36.999 ;
        RECT  0 36.441 0.018 36.459 ;
        RECT  0 35.901 0.018 35.919 ;
        RECT  0 35.361 0.018 35.379 ;
        RECT  0 34.821 0.018 34.839 ;
        RECT  0 34.281 0.018 34.299 ;
        RECT  0 33.741 0.018 33.759 ;
        RECT  0 33.201 0.018 33.219 ;
        RECT  0 32.661 0.018 32.679 ;
        RECT  0 32.121 0.018 32.139 ;
        RECT  0 31.581 0.018 31.599 ;
        RECT  0 31.041 0.018 31.059 ;
        RECT  0 30.501 0.018 30.519 ;
        RECT  0 29.961 0.018 29.979 ;
        RECT  0 29.421 0.018 29.439 ;
        RECT  0 28.881 0.018 28.899 ;
        RECT  0 28.341 0.018 28.359 ;
        RECT  0 27.801 0.018 27.819 ;
        RECT  0 27.261 0.018 27.279 ;
        RECT  0 26.721 0.018 26.739 ;
        RECT  0 26.181 0.018 26.199 ;
        RECT  0 25.641 0.018 25.659 ;
        RECT  0 25.101 0.018 25.119 ;
        RECT  0 24.561 0.018 24.579 ;
        RECT  0 24.021 0.018 24.039 ;
        RECT  0 23.481 0.018 23.499 ;
        RECT  0 22.941 0.018 22.959 ;
        RECT  0 22.401 0.018 22.419 ;
        RECT  0 21.861 0.018 21.879 ;
        RECT  0 21.321 0.018 21.339 ;
        RECT  0 20.781 0.018 20.799 ;
        RECT  0 20.241 0.018 20.259 ;
        RECT  0 19.701 0.018 19.719 ;
        RECT  0 19.161 0.018 19.179 ;
        RECT  0 18.621 0.018 18.639 ;
        RECT  0 18.081 0.018 18.099 ;
        RECT  0 17.541 0.018 17.559 ;
        RECT  0 17.001 0.018 17.019 ;
        RECT  0 16.461 0.018 16.479 ;
        RECT  0 15.921 0.018 15.939 ;
        RECT  0 15.381 0.018 15.399 ;
        RECT  0 14.841 0.018 14.859 ;
        RECT  0 14.301 0.018 14.319 ;
        RECT  0 13.761 0.018 13.779 ;
        RECT  0 13.221 0.018 13.239 ;
        RECT  0 12.681 0.018 12.699 ;
        RECT  0 12.141 0.018 12.159 ;
        RECT  0 11.601 0.018 11.619 ;
        RECT  0 11.061 0.018 11.079 ;
        RECT  0 10.521 0.018 10.539 ;
        RECT  0 9.981 0.018 9.999 ;
        RECT  0 9.441 0.018 9.459 ;
        RECT  0 8.901 0.018 8.919 ;
        RECT  0 8.361 0.018 8.379 ;
        RECT  0 7.821 0.018 7.839 ;
        RECT  0 7.281 0.018 7.299 ;
        RECT  0 6.741 0.018 6.759 ;
        RECT  0 6.201 0.018 6.219 ;
        RECT  0 5.661 0.018 5.679 ;
        RECT  0 5.121 0.018 5.139 ;
        RECT  0 4.581 0.018 4.599 ;
        RECT  0 4.041 0.018 4.059 ;
        RECT  0 3.501 0.018 3.519 ;
        RECT  0 2.961 0.018 2.979 ;
        RECT  0 2.421 0.018 2.439 ;
        RECT  0 1.881 0.018 1.899 ;
        RECT  0 1.341 0.018 1.359 ;
        RECT  0 0.801 0.018 0.819 ;
    END
  END VDD
  PIN VSS
    DIRECTION INOUT ;
    USE GROUND ;
    PORT
      LAYER M7 ;
        RECT  11.656 0.531 11.944 141.759 ;
        RECT  0.856 0.531 1.144 141.759 ;
      LAYER M6 ;
        RECT  0 141.396 0.032 141.684 ;
        RECT  0 135.996 0.032 136.284 ;
        RECT  0 130.596 0.032 130.884 ;
        RECT  0 125.196 0.032 125.484 ;
        RECT  0 119.796 0.032 120.084 ;
        RECT  0 114.396 0.032 114.684 ;
        RECT  0 108.996 0.032 109.284 ;
        RECT  0 103.596 0.032 103.884 ;
        RECT  0 98.196 0.032 98.484 ;
        RECT  0 92.796 0.032 93.084 ;
        RECT  0 87.396 0.032 87.684 ;
        RECT  0 81.996 0.032 82.284 ;
        RECT  0 76.596 0.032 76.884 ;
        RECT  0 71.196 0.032 71.484 ;
        RECT  0 65.796 0.032 66.084 ;
        RECT  0 60.396 0.032 60.684 ;
        RECT  0 54.996 0.032 55.284 ;
        RECT  0 49.596 0.032 49.884 ;
        RECT  0 44.196 0.032 44.484 ;
        RECT  0 38.796 0.032 39.084 ;
        RECT  0 33.396 0.032 33.684 ;
        RECT  0 27.996 0.032 28.284 ;
        RECT  0 22.596 0.032 22.884 ;
        RECT  0 17.196 0.032 17.484 ;
        RECT  0 11.796 0.032 12.084 ;
        RECT  0 6.396 0.032 6.684 ;
        RECT  0 0.996 0.032 1.284 ;
      LAYER M2 ;
        RECT  0 141.471 0.018 141.489 ;
        RECT  0 140.931 0.018 140.949 ;
        RECT  0 140.391 0.018 140.409 ;
        RECT  0 139.851 0.018 139.869 ;
        RECT  0 139.311 0.018 139.329 ;
        RECT  0 138.771 0.018 138.789 ;
        RECT  0 138.231 0.018 138.249 ;
        RECT  0 137.691 0.018 137.709 ;
        RECT  0 137.151 0.018 137.169 ;
        RECT  0 136.611 0.018 136.629 ;
        RECT  0 136.071 0.018 136.089 ;
        RECT  0 135.531 0.018 135.549 ;
        RECT  0 134.991 0.018 135.009 ;
        RECT  0 134.451 0.018 134.469 ;
        RECT  0 133.911 0.018 133.929 ;
        RECT  0 133.371 0.018 133.389 ;
        RECT  0 132.831 0.018 132.849 ;
        RECT  0 132.291 0.018 132.309 ;
        RECT  0 131.751 0.018 131.769 ;
        RECT  0 131.211 0.018 131.229 ;
        RECT  0 130.671 0.018 130.689 ;
        RECT  0 130.131 0.018 130.149 ;
        RECT  0 129.591 0.018 129.609 ;
        RECT  0 129.051 0.018 129.069 ;
        RECT  0 128.511 0.018 128.529 ;
        RECT  0 127.971 0.018 127.989 ;
        RECT  0 127.431 0.018 127.449 ;
        RECT  0 126.891 0.018 126.909 ;
        RECT  0 126.351 0.018 126.369 ;
        RECT  0 125.811 0.018 125.829 ;
        RECT  0 125.271 0.018 125.289 ;
        RECT  0 124.731 0.018 124.749 ;
        RECT  0 124.191 0.018 124.209 ;
        RECT  0 123.651 0.018 123.669 ;
        RECT  0 123.111 0.018 123.129 ;
        RECT  0 122.571 0.018 122.589 ;
        RECT  0 122.031 0.018 122.049 ;
        RECT  0 121.491 0.018 121.509 ;
        RECT  0 120.951 0.018 120.969 ;
        RECT  0 120.411 0.018 120.429 ;
        RECT  0 119.871 0.018 119.889 ;
        RECT  0 119.331 0.018 119.349 ;
        RECT  0 118.791 0.018 118.809 ;
        RECT  0 118.251 0.018 118.269 ;
        RECT  0 117.711 0.018 117.729 ;
        RECT  0 117.171 0.018 117.189 ;
        RECT  0 116.631 0.018 116.649 ;
        RECT  0 116.091 0.018 116.109 ;
        RECT  0 115.551 0.018 115.569 ;
        RECT  0 115.011 0.018 115.029 ;
        RECT  0 114.471 0.018 114.489 ;
        RECT  0 113.931 0.018 113.949 ;
        RECT  0 113.391 0.018 113.409 ;
        RECT  0 112.851 0.018 112.869 ;
        RECT  0 112.311 0.018 112.329 ;
        RECT  0 111.771 0.018 111.789 ;
        RECT  0 111.231 0.018 111.249 ;
        RECT  0 110.691 0.018 110.709 ;
        RECT  0 110.151 0.018 110.169 ;
        RECT  0 109.611 0.018 109.629 ;
        RECT  0 109.071 0.018 109.089 ;
        RECT  0 108.531 0.018 108.549 ;
        RECT  0 107.991 0.018 108.009 ;
        RECT  0 107.451 0.018 107.469 ;
        RECT  0 106.911 0.018 106.929 ;
        RECT  0 106.371 0.018 106.389 ;
        RECT  0 105.831 0.018 105.849 ;
        RECT  0 105.291 0.018 105.309 ;
        RECT  0 104.751 0.018 104.769 ;
        RECT  0 104.211 0.018 104.229 ;
        RECT  0 103.671 0.018 103.689 ;
        RECT  0 103.131 0.018 103.149 ;
        RECT  0 102.591 0.018 102.609 ;
        RECT  0 102.051 0.018 102.069 ;
        RECT  0 101.511 0.018 101.529 ;
        RECT  0 100.971 0.018 100.989 ;
        RECT  0 100.431 0.018 100.449 ;
        RECT  0 99.891 0.018 99.909 ;
        RECT  0 99.351 0.018 99.369 ;
        RECT  0 98.811 0.018 98.829 ;
        RECT  0 98.271 0.018 98.289 ;
        RECT  0 97.731 0.018 97.749 ;
        RECT  0 97.191 0.018 97.209 ;
        RECT  0 96.651 0.018 96.669 ;
        RECT  0 96.111 0.018 96.129 ;
        RECT  0 95.571 0.018 95.589 ;
        RECT  0 95.031 0.018 95.049 ;
        RECT  0 94.491 0.018 94.509 ;
        RECT  0 93.951 0.018 93.969 ;
        RECT  0 93.411 0.018 93.429 ;
        RECT  0 92.871 0.018 92.889 ;
        RECT  0 92.331 0.018 92.349 ;
        RECT  0 91.791 0.018 91.809 ;
        RECT  0 91.251 0.018 91.269 ;
        RECT  0 90.711 0.018 90.729 ;
        RECT  0 90.171 0.018 90.189 ;
        RECT  0 89.631 0.018 89.649 ;
        RECT  0 89.091 0.018 89.109 ;
        RECT  0 88.551 0.018 88.569 ;
        RECT  0 88.011 0.018 88.029 ;
        RECT  0 87.471 0.018 87.489 ;
        RECT  0 86.931 0.018 86.949 ;
        RECT  0 86.391 0.018 86.409 ;
        RECT  0 85.851 0.018 85.869 ;
        RECT  0 85.311 0.018 85.329 ;
        RECT  0 84.771 0.018 84.789 ;
        RECT  0 84.231 0.018 84.249 ;
        RECT  0 83.691 0.018 83.709 ;
        RECT  0 83.151 0.018 83.169 ;
        RECT  0 82.611 0.018 82.629 ;
        RECT  0 82.071 0.018 82.089 ;
        RECT  0 81.531 0.018 81.549 ;
        RECT  0 80.991 0.018 81.009 ;
        RECT  0 80.451 0.018 80.469 ;
        RECT  0 79.911 0.018 79.929 ;
        RECT  0 79.371 0.018 79.389 ;
        RECT  0 78.831 0.018 78.849 ;
        RECT  0 78.291 0.018 78.309 ;
        RECT  0 77.751 0.018 77.769 ;
        RECT  0 77.211 0.018 77.229 ;
        RECT  0 76.671 0.018 76.689 ;
        RECT  0 76.131 0.018 76.149 ;
        RECT  0 75.591 0.018 75.609 ;
        RECT  0 75.051 0.018 75.069 ;
        RECT  0 74.511 0.018 74.529 ;
        RECT  0 73.971 0.018 73.989 ;
        RECT  0 73.431 0.018 73.449 ;
        RECT  0 72.891 0.018 72.909 ;
        RECT  0 72.351 0.018 72.369 ;
        RECT  0 71.811 0.018 71.829 ;
        RECT  0 71.271 0.018 71.289 ;
        RECT  0 70.731 0.018 70.749 ;
        RECT  0 70.191 0.018 70.209 ;
        RECT  0 69.651 0.018 69.669 ;
        RECT  0 69.111 0.018 69.129 ;
        RECT  0 68.571 0.018 68.589 ;
        RECT  0 68.031 0.018 68.049 ;
        RECT  0 67.491 0.018 67.509 ;
        RECT  0 66.951 0.018 66.969 ;
        RECT  0 66.411 0.018 66.429 ;
        RECT  0 65.871 0.018 65.889 ;
        RECT  0 65.331 0.018 65.349 ;
        RECT  0 64.791 0.018 64.809 ;
        RECT  0 64.251 0.018 64.269 ;
        RECT  0 63.711 0.018 63.729 ;
        RECT  0 63.171 0.018 63.189 ;
        RECT  0 62.631 0.018 62.649 ;
        RECT  0 62.091 0.018 62.109 ;
        RECT  0 61.551 0.018 61.569 ;
        RECT  0 61.011 0.018 61.029 ;
        RECT  0 60.471 0.018 60.489 ;
        RECT  0 59.931 0.018 59.949 ;
        RECT  0 59.391 0.018 59.409 ;
        RECT  0 58.851 0.018 58.869 ;
        RECT  0 58.311 0.018 58.329 ;
        RECT  0 57.771 0.018 57.789 ;
        RECT  0 57.231 0.018 57.249 ;
        RECT  0 56.691 0.018 56.709 ;
        RECT  0 56.151 0.018 56.169 ;
        RECT  0 55.611 0.018 55.629 ;
        RECT  0 55.071 0.018 55.089 ;
        RECT  0 54.531 0.018 54.549 ;
        RECT  0 53.991 0.018 54.009 ;
        RECT  0 53.451 0.018 53.469 ;
        RECT  0 52.911 0.018 52.929 ;
        RECT  0 52.371 0.018 52.389 ;
        RECT  0 51.831 0.018 51.849 ;
        RECT  0 51.291 0.018 51.309 ;
        RECT  0 50.751 0.018 50.769 ;
        RECT  0 50.211 0.018 50.229 ;
        RECT  0 49.671 0.018 49.689 ;
        RECT  0 49.131 0.018 49.149 ;
        RECT  0 48.591 0.018 48.609 ;
        RECT  0 48.051 0.018 48.069 ;
        RECT  0 47.511 0.018 47.529 ;
        RECT  0 46.971 0.018 46.989 ;
        RECT  0 46.431 0.018 46.449 ;
        RECT  0 45.891 0.018 45.909 ;
        RECT  0 45.351 0.018 45.369 ;
        RECT  0 44.811 0.018 44.829 ;
        RECT  0 44.271 0.018 44.289 ;
        RECT  0 43.731 0.018 43.749 ;
        RECT  0 43.191 0.018 43.209 ;
        RECT  0 42.651 0.018 42.669 ;
        RECT  0 42.111 0.018 42.129 ;
        RECT  0 41.571 0.018 41.589 ;
        RECT  0 41.031 0.018 41.049 ;
        RECT  0 40.491 0.018 40.509 ;
        RECT  0 39.951 0.018 39.969 ;
        RECT  0 39.411 0.018 39.429 ;
        RECT  0 38.871 0.018 38.889 ;
        RECT  0 38.331 0.018 38.349 ;
        RECT  0 37.791 0.018 37.809 ;
        RECT  0 37.251 0.018 37.269 ;
        RECT  0 36.711 0.018 36.729 ;
        RECT  0 36.171 0.018 36.189 ;
        RECT  0 35.631 0.018 35.649 ;
        RECT  0 35.091 0.018 35.109 ;
        RECT  0 34.551 0.018 34.569 ;
        RECT  0 34.011 0.018 34.029 ;
        RECT  0 33.471 0.018 33.489 ;
        RECT  0 32.931 0.018 32.949 ;
        RECT  0 32.391 0.018 32.409 ;
        RECT  0 31.851 0.018 31.869 ;
        RECT  0 31.311 0.018 31.329 ;
        RECT  0 30.771 0.018 30.789 ;
        RECT  0 30.231 0.018 30.249 ;
        RECT  0 29.691 0.018 29.709 ;
        RECT  0 29.151 0.018 29.169 ;
        RECT  0 28.611 0.018 28.629 ;
        RECT  0 28.071 0.018 28.089 ;
        RECT  0 27.531 0.018 27.549 ;
        RECT  0 26.991 0.018 27.009 ;
        RECT  0 26.451 0.018 26.469 ;
        RECT  0 25.911 0.018 25.929 ;
        RECT  0 25.371 0.018 25.389 ;
        RECT  0 24.831 0.018 24.849 ;
        RECT  0 24.291 0.018 24.309 ;
        RECT  0 23.751 0.018 23.769 ;
        RECT  0 23.211 0.018 23.229 ;
        RECT  0 22.671 0.018 22.689 ;
        RECT  0 22.131 0.018 22.149 ;
        RECT  0 21.591 0.018 21.609 ;
        RECT  0 21.051 0.018 21.069 ;
        RECT  0 20.511 0.018 20.529 ;
        RECT  0 19.971 0.018 19.989 ;
        RECT  0 19.431 0.018 19.449 ;
        RECT  0 18.891 0.018 18.909 ;
        RECT  0 18.351 0.018 18.369 ;
        RECT  0 17.811 0.018 17.829 ;
        RECT  0 17.271 0.018 17.289 ;
        RECT  0 16.731 0.018 16.749 ;
        RECT  0 16.191 0.018 16.209 ;
        RECT  0 15.651 0.018 15.669 ;
        RECT  0 15.111 0.018 15.129 ;
        RECT  0 14.571 0.018 14.589 ;
        RECT  0 14.031 0.018 14.049 ;
        RECT  0 13.491 0.018 13.509 ;
        RECT  0 12.951 0.018 12.969 ;
        RECT  0 12.411 0.018 12.429 ;
        RECT  0 11.871 0.018 11.889 ;
        RECT  0 11.331 0.018 11.349 ;
        RECT  0 10.791 0.018 10.809 ;
        RECT  0 10.251 0.018 10.269 ;
        RECT  0 9.711 0.018 9.729 ;
        RECT  0 9.171 0.018 9.189 ;
        RECT  0 8.631 0.018 8.649 ;
        RECT  0 8.091 0.018 8.109 ;
        RECT  0 7.551 0.018 7.569 ;
        RECT  0 7.011 0.018 7.029 ;
        RECT  0 6.471 0.018 6.489 ;
        RECT  0 5.931 0.018 5.949 ;
        RECT  0 5.391 0.018 5.409 ;
        RECT  0 4.851 0.018 4.869 ;
        RECT  0 4.311 0.018 4.329 ;
        RECT  0 3.771 0.018 3.789 ;
        RECT  0 3.231 0.018 3.249 ;
        RECT  0 2.691 0.018 2.709 ;
        RECT  0 2.151 0.018 2.169 ;
        RECT  0 1.611 0.018 1.629 ;
        RECT  0 1.071 0.018 1.089 ;
        RECT  0 0.531 0.018 0.549 ;
      LAYER M1 ;
        RECT  0 141.471 0.018 141.489 ;
        RECT  0 140.931 0.018 140.949 ;
        RECT  0 140.391 0.018 140.409 ;
        RECT  0 139.851 0.018 139.869 ;
        RECT  0 139.311 0.018 139.329 ;
        RECT  0 138.771 0.018 138.789 ;
        RECT  0 138.231 0.018 138.249 ;
        RECT  0 137.691 0.018 137.709 ;
        RECT  0 137.151 0.018 137.169 ;
        RECT  0 136.611 0.018 136.629 ;
        RECT  0 136.071 0.018 136.089 ;
        RECT  0 135.531 0.018 135.549 ;
        RECT  0 134.991 0.018 135.009 ;
        RECT  0 134.451 0.018 134.469 ;
        RECT  0 133.911 0.018 133.929 ;
        RECT  0 133.371 0.018 133.389 ;
        RECT  0 132.831 0.018 132.849 ;
        RECT  0 132.291 0.018 132.309 ;
        RECT  0 131.751 0.018 131.769 ;
        RECT  0 131.211 0.018 131.229 ;
        RECT  0 130.671 0.018 130.689 ;
        RECT  0 130.131 0.018 130.149 ;
        RECT  0 129.591 0.018 129.609 ;
        RECT  0 129.051 0.018 129.069 ;
        RECT  0 128.511 0.018 128.529 ;
        RECT  0 127.971 0.018 127.989 ;
        RECT  0 127.431 0.018 127.449 ;
        RECT  0 126.891 0.018 126.909 ;
        RECT  0 126.351 0.018 126.369 ;
        RECT  0 125.811 0.018 125.829 ;
        RECT  0 125.271 0.018 125.289 ;
        RECT  0 124.731 0.018 124.749 ;
        RECT  0 124.191 0.018 124.209 ;
        RECT  0 123.651 0.018 123.669 ;
        RECT  0 123.111 0.018 123.129 ;
        RECT  0 122.571 0.018 122.589 ;
        RECT  0 122.031 0.018 122.049 ;
        RECT  0 121.491 0.018 121.509 ;
        RECT  0 120.951 0.018 120.969 ;
        RECT  0 120.411 0.018 120.429 ;
        RECT  0 119.871 0.018 119.889 ;
        RECT  0 119.331 0.018 119.349 ;
        RECT  0 118.791 0.018 118.809 ;
        RECT  0 118.251 0.018 118.269 ;
        RECT  0 117.711 0.018 117.729 ;
        RECT  0 117.171 0.018 117.189 ;
        RECT  0 116.631 0.018 116.649 ;
        RECT  0 116.091 0.018 116.109 ;
        RECT  0 115.551 0.018 115.569 ;
        RECT  0 115.011 0.018 115.029 ;
        RECT  0 114.471 0.018 114.489 ;
        RECT  0 113.931 0.018 113.949 ;
        RECT  0 113.391 0.018 113.409 ;
        RECT  0 112.851 0.018 112.869 ;
        RECT  0 112.311 0.018 112.329 ;
        RECT  0 111.771 0.018 111.789 ;
        RECT  0 111.231 0.018 111.249 ;
        RECT  0 110.691 0.018 110.709 ;
        RECT  0 110.151 0.018 110.169 ;
        RECT  0 109.611 0.018 109.629 ;
        RECT  0 109.071 0.018 109.089 ;
        RECT  0 108.531 0.018 108.549 ;
        RECT  0 107.991 0.018 108.009 ;
        RECT  0 107.451 0.018 107.469 ;
        RECT  0 106.911 0.018 106.929 ;
        RECT  0 106.371 0.018 106.389 ;
        RECT  0 105.831 0.018 105.849 ;
        RECT  0 105.291 0.018 105.309 ;
        RECT  0 104.751 0.018 104.769 ;
        RECT  0 104.211 0.018 104.229 ;
        RECT  0 103.671 0.018 103.689 ;
        RECT  0 103.131 0.018 103.149 ;
        RECT  0 102.591 0.018 102.609 ;
        RECT  0 102.051 0.018 102.069 ;
        RECT  0 101.511 0.018 101.529 ;
        RECT  0 100.971 0.018 100.989 ;
        RECT  0 100.431 0.018 100.449 ;
        RECT  0 99.891 0.018 99.909 ;
        RECT  0 99.351 0.018 99.369 ;
        RECT  0 98.811 0.018 98.829 ;
        RECT  0 98.271 0.018 98.289 ;
        RECT  0 97.731 0.018 97.749 ;
        RECT  0 97.191 0.018 97.209 ;
        RECT  0 96.651 0.018 96.669 ;
        RECT  0 96.111 0.018 96.129 ;
        RECT  0 95.571 0.018 95.589 ;
        RECT  0 95.031 0.018 95.049 ;
        RECT  0 94.491 0.018 94.509 ;
        RECT  0 93.951 0.018 93.969 ;
        RECT  0 93.411 0.018 93.429 ;
        RECT  0 92.871 0.018 92.889 ;
        RECT  0 92.331 0.018 92.349 ;
        RECT  0 91.791 0.018 91.809 ;
        RECT  0 91.251 0.018 91.269 ;
        RECT  0 90.711 0.018 90.729 ;
        RECT  0 90.171 0.018 90.189 ;
        RECT  0 89.631 0.018 89.649 ;
        RECT  0 89.091 0.018 89.109 ;
        RECT  0 88.551 0.018 88.569 ;
        RECT  0 88.011 0.018 88.029 ;
        RECT  0 87.471 0.018 87.489 ;
        RECT  0 86.931 0.018 86.949 ;
        RECT  0 86.391 0.018 86.409 ;
        RECT  0 85.851 0.018 85.869 ;
        RECT  0 85.311 0.018 85.329 ;
        RECT  0 84.771 0.018 84.789 ;
        RECT  0 84.231 0.018 84.249 ;
        RECT  0 83.691 0.018 83.709 ;
        RECT  0 83.151 0.018 83.169 ;
        RECT  0 82.611 0.018 82.629 ;
        RECT  0 82.071 0.018 82.089 ;
        RECT  0 81.531 0.018 81.549 ;
        RECT  0 80.991 0.018 81.009 ;
        RECT  0 80.451 0.018 80.469 ;
        RECT  0 79.911 0.018 79.929 ;
        RECT  0 79.371 0.018 79.389 ;
        RECT  0 78.831 0.018 78.849 ;
        RECT  0 78.291 0.018 78.309 ;
        RECT  0 77.751 0.018 77.769 ;
        RECT  0 77.211 0.018 77.229 ;
        RECT  0 76.671 0.018 76.689 ;
        RECT  0 76.131 0.018 76.149 ;
        RECT  0 75.591 0.018 75.609 ;
        RECT  0 75.051 0.018 75.069 ;
        RECT  0 74.511 0.018 74.529 ;
        RECT  0 73.971 0.018 73.989 ;
        RECT  0 73.431 0.018 73.449 ;
        RECT  0 72.891 0.018 72.909 ;
        RECT  0 72.351 0.018 72.369 ;
        RECT  0 71.811 0.018 71.829 ;
        RECT  0 71.271 0.018 71.289 ;
        RECT  0 70.731 0.018 70.749 ;
        RECT  0 70.191 0.018 70.209 ;
        RECT  0 69.651 0.018 69.669 ;
        RECT  0 69.111 0.018 69.129 ;
        RECT  0 68.571 0.018 68.589 ;
        RECT  0 68.031 0.018 68.049 ;
        RECT  0 67.491 0.018 67.509 ;
        RECT  0 66.951 0.018 66.969 ;
        RECT  0 66.411 0.018 66.429 ;
        RECT  0 65.871 0.018 65.889 ;
        RECT  0 65.331 0.018 65.349 ;
        RECT  0 64.791 0.018 64.809 ;
        RECT  0 64.251 0.018 64.269 ;
        RECT  0 63.711 0.018 63.729 ;
        RECT  0 63.171 0.018 63.189 ;
        RECT  0 62.631 0.018 62.649 ;
        RECT  0 62.091 0.018 62.109 ;
        RECT  0 61.551 0.018 61.569 ;
        RECT  0 61.011 0.018 61.029 ;
        RECT  0 60.471 0.018 60.489 ;
        RECT  0 59.931 0.018 59.949 ;
        RECT  0 59.391 0.018 59.409 ;
        RECT  0 58.851 0.018 58.869 ;
        RECT  0 58.311 0.018 58.329 ;
        RECT  0 57.771 0.018 57.789 ;
        RECT  0 57.231 0.018 57.249 ;
        RECT  0 56.691 0.018 56.709 ;
        RECT  0 56.151 0.018 56.169 ;
        RECT  0 55.611 0.018 55.629 ;
        RECT  0 55.071 0.018 55.089 ;
        RECT  0 54.531 0.018 54.549 ;
        RECT  0 53.991 0.018 54.009 ;
        RECT  0 53.451 0.018 53.469 ;
        RECT  0 52.911 0.018 52.929 ;
        RECT  0 52.371 0.018 52.389 ;
        RECT  0 51.831 0.018 51.849 ;
        RECT  0 51.291 0.018 51.309 ;
        RECT  0 50.751 0.018 50.769 ;
        RECT  0 50.211 0.018 50.229 ;
        RECT  0 49.671 0.018 49.689 ;
        RECT  0 49.131 0.018 49.149 ;
        RECT  0 48.591 0.018 48.609 ;
        RECT  0 48.051 0.018 48.069 ;
        RECT  0 47.511 0.018 47.529 ;
        RECT  0 46.971 0.018 46.989 ;
        RECT  0 46.431 0.018 46.449 ;
        RECT  0 45.891 0.018 45.909 ;
        RECT  0 45.351 0.018 45.369 ;
        RECT  0 44.811 0.018 44.829 ;
        RECT  0 44.271 0.018 44.289 ;
        RECT  0 43.731 0.018 43.749 ;
        RECT  0 43.191 0.018 43.209 ;
        RECT  0 42.651 0.018 42.669 ;
        RECT  0 42.111 0.018 42.129 ;
        RECT  0 41.571 0.018 41.589 ;
        RECT  0 41.031 0.018 41.049 ;
        RECT  0 40.491 0.018 40.509 ;
        RECT  0 39.951 0.018 39.969 ;
        RECT  0 39.411 0.018 39.429 ;
        RECT  0 38.871 0.018 38.889 ;
        RECT  0 38.331 0.018 38.349 ;
        RECT  0 37.791 0.018 37.809 ;
        RECT  0 37.251 0.018 37.269 ;
        RECT  0 36.711 0.018 36.729 ;
        RECT  0 36.171 0.018 36.189 ;
        RECT  0 35.631 0.018 35.649 ;
        RECT  0 35.091 0.018 35.109 ;
        RECT  0 34.551 0.018 34.569 ;
        RECT  0 34.011 0.018 34.029 ;
        RECT  0 33.471 0.018 33.489 ;
        RECT  0 32.931 0.018 32.949 ;
        RECT  0 32.391 0.018 32.409 ;
        RECT  0 31.851 0.018 31.869 ;
        RECT  0 31.311 0.018 31.329 ;
        RECT  0 30.771 0.018 30.789 ;
        RECT  0 30.231 0.018 30.249 ;
        RECT  0 29.691 0.018 29.709 ;
        RECT  0 29.151 0.018 29.169 ;
        RECT  0 28.611 0.018 28.629 ;
        RECT  0 28.071 0.018 28.089 ;
        RECT  0 27.531 0.018 27.549 ;
        RECT  0 26.991 0.018 27.009 ;
        RECT  0 26.451 0.018 26.469 ;
        RECT  0 25.911 0.018 25.929 ;
        RECT  0 25.371 0.018 25.389 ;
        RECT  0 24.831 0.018 24.849 ;
        RECT  0 24.291 0.018 24.309 ;
        RECT  0 23.751 0.018 23.769 ;
        RECT  0 23.211 0.018 23.229 ;
        RECT  0 22.671 0.018 22.689 ;
        RECT  0 22.131 0.018 22.149 ;
        RECT  0 21.591 0.018 21.609 ;
        RECT  0 21.051 0.018 21.069 ;
        RECT  0 20.511 0.018 20.529 ;
        RECT  0 19.971 0.018 19.989 ;
        RECT  0 19.431 0.018 19.449 ;
        RECT  0 18.891 0.018 18.909 ;
        RECT  0 18.351 0.018 18.369 ;
        RECT  0 17.811 0.018 17.829 ;
        RECT  0 17.271 0.018 17.289 ;
        RECT  0 16.731 0.018 16.749 ;
        RECT  0 16.191 0.018 16.209 ;
        RECT  0 15.651 0.018 15.669 ;
        RECT  0 15.111 0.018 15.129 ;
        RECT  0 14.571 0.018 14.589 ;
        RECT  0 14.031 0.018 14.049 ;
        RECT  0 13.491 0.018 13.509 ;
        RECT  0 12.951 0.018 12.969 ;
        RECT  0 12.411 0.018 12.429 ;
        RECT  0 11.871 0.018 11.889 ;
        RECT  0 11.331 0.018 11.349 ;
        RECT  0 10.791 0.018 10.809 ;
        RECT  0 10.251 0.018 10.269 ;
        RECT  0 9.711 0.018 9.729 ;
        RECT  0 9.171 0.018 9.189 ;
        RECT  0 8.631 0.018 8.649 ;
        RECT  0 8.091 0.018 8.109 ;
        RECT  0 7.551 0.018 7.569 ;
        RECT  0 7.011 0.018 7.029 ;
        RECT  0 6.471 0.018 6.489 ;
        RECT  0 5.931 0.018 5.949 ;
        RECT  0 5.391 0.018 5.409 ;
        RECT  0 4.851 0.018 4.869 ;
        RECT  0 4.311 0.018 4.329 ;
        RECT  0 3.771 0.018 3.789 ;
        RECT  0 3.231 0.018 3.249 ;
        RECT  0 2.691 0.018 2.709 ;
        RECT  0 2.151 0.018 2.169 ;
        RECT  0 1.611 0.018 1.629 ;
        RECT  0 1.071 0.018 1.089 ;
        RECT  0 0.531 0.018 0.549 ;
    END
  END VSS
  OBS
    LAYER RVTN ;
     RECT  0 0.54 14.634 0.675 ;
     RECT  0 0.945 14.634 1.215 ;
     RECT  0 1.485 14.634 1.755 ;
     RECT  0 2.025 14.634 2.295 ;
     RECT  0 2.565 14.634 2.835 ;
     RECT  0 3.105 14.634 3.375 ;
     RECT  0 3.645 14.634 3.915 ;
     RECT  0 4.185 14.634 4.455 ;
     RECT  0 4.725 14.634 4.995 ;
     RECT  0 5.265 14.634 5.535 ;
     RECT  0 5.805 14.634 6.075 ;
     RECT  0 6.345 14.634 6.615 ;
     RECT  0 6.885 14.634 7.155 ;
     RECT  0 7.425 14.634 7.695 ;
     RECT  0 7.965 14.634 8.235 ;
     RECT  0 8.505 14.634 8.775 ;
     RECT  0 9.045 14.634 9.315 ;
     RECT  0 9.585 14.634 9.855 ;
     RECT  0 10.125 14.634 10.395 ;
     RECT  0 10.665 14.634 10.935 ;
     RECT  0 11.205 14.634 11.475 ;
     RECT  0 11.745 14.634 12.015 ;
     RECT  0 12.285 14.634 12.555 ;
     RECT  0 12.825 14.634 13.095 ;
     RECT  0 13.365 14.634 13.635 ;
     RECT  0 13.905 14.634 14.175 ;
     RECT  0 14.445 14.634 14.715 ;
     RECT  0 14.985 14.634 15.255 ;
     RECT  0 15.525 14.634 15.795 ;
     RECT  0 16.065 14.634 16.335 ;
     RECT  0 16.605 14.634 16.875 ;
     RECT  0 17.145 14.634 17.415 ;
     RECT  0 17.685 14.634 17.955 ;
     RECT  0 18.225 14.634 18.495 ;
     RECT  0 18.765 14.634 19.035 ;
     RECT  0 19.305 14.634 19.575 ;
     RECT  0 19.845 14.634 20.115 ;
     RECT  0 20.385 14.634 20.655 ;
     RECT  0 20.925 14.634 21.195 ;
     RECT  0 21.465 14.634 21.735 ;
     RECT  0 22.005 14.634 22.275 ;
     RECT  0 22.545 14.634 22.815 ;
     RECT  0 23.085 14.634 23.355 ;
     RECT  0 23.625 14.634 23.895 ;
     RECT  0 24.165 14.634 24.435 ;
     RECT  0 24.705 14.634 24.975 ;
     RECT  0 25.245 14.634 25.515 ;
     RECT  0 25.785 14.634 26.055 ;
     RECT  0 26.325 14.634 26.595 ;
     RECT  0 26.865 14.634 27.135 ;
     RECT  0 27.405 14.634 27.675 ;
     RECT  0 27.945 14.634 28.215 ;
     RECT  0 28.485 14.634 28.755 ;
     RECT  0 29.025 14.634 29.295 ;
     RECT  0 29.565 14.634 29.835 ;
     RECT  0 30.105 14.634 30.375 ;
     RECT  0 30.645 14.634 30.915 ;
     RECT  0 31.185 14.634 31.455 ;
     RECT  0 31.725 14.634 31.995 ;
     RECT  0 32.265 14.634 32.535 ;
     RECT  0 32.805 14.634 33.075 ;
     RECT  0 33.345 14.634 33.615 ;
     RECT  0 33.885 14.634 34.155 ;
     RECT  0 34.425 14.634 34.695 ;
     RECT  0 34.965 14.634 35.235 ;
     RECT  0 35.505 14.634 35.775 ;
     RECT  0 36.045 14.634 36.315 ;
     RECT  0 36.585 14.634 36.855 ;
     RECT  0 37.125 14.634 37.395 ;
     RECT  0 37.665 14.634 37.935 ;
     RECT  0 38.205 14.634 38.475 ;
     RECT  0 38.745 14.634 39.015 ;
     RECT  0 39.285 14.634 39.555 ;
     RECT  0 39.825 14.634 40.095 ;
     RECT  0 40.365 14.634 40.635 ;
     RECT  0 40.905 14.634 41.175 ;
     RECT  0 41.445 14.634 41.715 ;
     RECT  0 41.985 14.634 42.255 ;
     RECT  0 42.525 14.634 42.795 ;
     RECT  0 43.065 14.634 43.335 ;
     RECT  0 43.605 14.634 43.875 ;
     RECT  0 44.145 14.634 44.415 ;
     RECT  0 44.685 14.634 44.955 ;
     RECT  0 45.225 14.634 45.495 ;
     RECT  0 45.765 14.634 46.035 ;
     RECT  0 46.305 14.634 46.575 ;
     RECT  0 46.845 14.634 47.115 ;
     RECT  0 47.385 14.634 47.655 ;
     RECT  0 47.925 14.634 48.195 ;
     RECT  0 48.465 14.634 48.735 ;
     RECT  0 49.005 14.634 49.275 ;
     RECT  0 49.545 14.634 49.815 ;
     RECT  0 50.085 14.634 50.355 ;
     RECT  0 50.625 14.634 50.895 ;
     RECT  0 51.165 14.634 51.435 ;
     RECT  0 51.705 14.634 51.975 ;
     RECT  0 52.245 14.634 52.515 ;
     RECT  0 52.785 14.634 53.055 ;
     RECT  0 53.325 14.634 53.595 ;
     RECT  0 53.865 14.634 54.135 ;
     RECT  0 54.405 14.634 54.675 ;
     RECT  0 54.945 14.634 55.215 ;
     RECT  0 55.485 14.634 55.755 ;
     RECT  0 56.025 14.634 56.295 ;
     RECT  0 56.565 14.634 56.835 ;
     RECT  0 57.105 14.634 57.375 ;
     RECT  0 57.645 14.634 57.915 ;
     RECT  0 58.185 14.634 58.455 ;
     RECT  0 58.725 14.634 58.995 ;
     RECT  0 59.265 14.634 59.535 ;
     RECT  0 59.805 14.634 60.075 ;
     RECT  0 60.345 14.634 60.615 ;
     RECT  0 60.885 14.634 61.155 ;
     RECT  0 61.425 14.634 61.695 ;
     RECT  0 61.965 14.634 62.235 ;
     RECT  0 62.505 14.634 62.775 ;
     RECT  0 63.045 14.634 63.315 ;
     RECT  0 63.585 14.634 63.855 ;
     RECT  0 64.125 14.634 64.395 ;
     RECT  0 64.665 14.634 64.935 ;
     RECT  0 65.205 14.634 65.475 ;
     RECT  0 65.745 14.634 66.015 ;
     RECT  0 66.285 14.634 66.555 ;
     RECT  0 66.825 14.634 67.095 ;
     RECT  0 67.365 14.634 67.635 ;
     RECT  0 67.905 14.634 68.175 ;
     RECT  0 68.445 14.634 68.715 ;
     RECT  0 68.985 14.634 69.255 ;
     RECT  0 69.525 14.634 69.795 ;
     RECT  0 70.065 14.634 70.335 ;
     RECT  0 70.605 14.634 70.875 ;
     RECT  0 71.145 14.634 71.415 ;
     RECT  0 71.685 14.634 71.955 ;
     RECT  0 72.225 14.634 72.495 ;
     RECT  0 72.765 14.634 73.035 ;
     RECT  0 73.305 14.634 73.575 ;
     RECT  0 73.845 14.634 74.115 ;
     RECT  0 74.385 14.634 74.655 ;
     RECT  0 74.925 14.634 75.195 ;
     RECT  0 75.465 14.634 75.735 ;
     RECT  0 76.005 14.634 76.275 ;
     RECT  0 76.545 14.634 76.815 ;
     RECT  0 77.085 14.634 77.355 ;
     RECT  0 77.625 14.634 77.895 ;
     RECT  0 78.165 14.634 78.435 ;
     RECT  0 78.705 14.634 78.975 ;
     RECT  0 79.245 14.634 79.515 ;
     RECT  0 79.785 14.634 80.055 ;
     RECT  0 80.325 14.634 80.595 ;
     RECT  0 80.865 14.634 81.135 ;
     RECT  0 81.405 14.634 81.675 ;
     RECT  0 81.945 14.634 82.215 ;
     RECT  0 82.485 14.634 82.755 ;
     RECT  0 83.025 14.634 83.295 ;
     RECT  0 83.565 14.634 83.835 ;
     RECT  0 84.105 14.634 84.375 ;
     RECT  0 84.645 14.634 84.915 ;
     RECT  0 85.185 14.634 85.455 ;
     RECT  0 85.725 14.634 85.995 ;
     RECT  0 86.265 14.634 86.535 ;
     RECT  0 86.805 14.634 87.075 ;
     RECT  0 87.345 14.634 87.615 ;
     RECT  0 87.885 14.634 88.155 ;
     RECT  0 88.425 14.634 88.695 ;
     RECT  0 88.965 14.634 89.235 ;
     RECT  0 89.505 14.634 89.775 ;
     RECT  0 90.045 14.634 90.315 ;
     RECT  0 90.585 14.634 90.855 ;
     RECT  0 91.125 14.634 91.395 ;
     RECT  0 91.665 14.634 91.935 ;
     RECT  0 92.205 14.634 92.475 ;
     RECT  0 92.745 14.634 93.015 ;
     RECT  0 93.285 14.634 93.555 ;
     RECT  0 93.825 14.634 94.095 ;
     RECT  0 94.365 14.634 94.635 ;
     RECT  0 94.905 14.634 95.175 ;
     RECT  0 95.445 14.634 95.715 ;
     RECT  0 95.985 14.634 96.255 ;
     RECT  0 96.525 14.634 96.795 ;
     RECT  0 97.065 14.634 97.335 ;
     RECT  0 97.605 14.634 97.875 ;
     RECT  0 98.145 14.634 98.415 ;
     RECT  0 98.685 14.634 98.955 ;
     RECT  0 99.225 14.634 99.495 ;
     RECT  0 99.765 14.634 100.035 ;
     RECT  0 100.305 14.634 100.575 ;
     RECT  0 100.845 14.634 101.115 ;
     RECT  0 101.385 14.634 101.655 ;
     RECT  0 101.925 14.634 102.195 ;
     RECT  0 102.465 14.634 102.735 ;
     RECT  0 103.005 14.634 103.275 ;
     RECT  0 103.545 14.634 103.815 ;
     RECT  0 104.085 14.634 104.355 ;
     RECT  0 104.625 14.634 104.895 ;
     RECT  0 105.165 14.634 105.435 ;
     RECT  0 105.705 14.634 105.975 ;
     RECT  0 106.245 14.634 106.515 ;
     RECT  0 106.785 14.634 107.055 ;
     RECT  0 107.325 14.634 107.595 ;
     RECT  0 107.865 14.634 108.135 ;
     RECT  0 108.405 14.634 108.675 ;
     RECT  0 108.945 14.634 109.215 ;
     RECT  0 109.485 14.634 109.755 ;
     RECT  0 110.025 14.634 110.295 ;
     RECT  0 110.565 14.634 110.835 ;
     RECT  0 111.105 14.634 111.375 ;
     RECT  0 111.645 14.634 111.915 ;
     RECT  0 112.185 14.634 112.455 ;
     RECT  0 112.725 14.634 112.995 ;
     RECT  0 113.265 14.634 113.535 ;
     RECT  0 113.805 14.634 114.075 ;
     RECT  0 114.345 14.634 114.615 ;
     RECT  0 114.885 14.634 115.155 ;
     RECT  0 115.425 14.634 115.695 ;
     RECT  0 115.965 14.634 116.235 ;
     RECT  0 116.505 14.634 116.775 ;
     RECT  0 117.045 14.634 117.315 ;
     RECT  0 117.585 14.634 117.855 ;
     RECT  0 118.125 14.634 118.395 ;
     RECT  0 118.665 14.634 118.935 ;
     RECT  0 119.205 14.634 119.475 ;
     RECT  0 119.745 14.634 120.015 ;
     RECT  0 120.285 14.634 120.555 ;
     RECT  0 120.825 14.634 121.095 ;
     RECT  0 121.365 14.634 121.635 ;
     RECT  0 121.905 14.634 122.175 ;
     RECT  0 122.445 14.634 122.715 ;
     RECT  0 122.985 14.634 123.255 ;
     RECT  0 123.525 14.634 123.795 ;
     RECT  0 124.065 14.634 124.335 ;
     RECT  0 124.605 14.634 124.875 ;
     RECT  0 125.145 14.634 125.415 ;
     RECT  0 125.685 14.634 125.955 ;
     RECT  0 126.225 14.634 126.495 ;
     RECT  0 126.765 14.634 127.035 ;
     RECT  0 127.305 14.634 127.575 ;
     RECT  0 127.845 14.634 128.115 ;
     RECT  0 128.385 14.634 128.655 ;
     RECT  0 128.925 14.634 129.195 ;
     RECT  0 129.465 14.634 129.735 ;
     RECT  0 130.005 14.634 130.275 ;
     RECT  0 130.545 14.634 130.815 ;
     RECT  0 131.085 14.634 131.355 ;
     RECT  0 131.625 14.634 131.895 ;
     RECT  0 132.165 14.634 132.435 ;
     RECT  0 132.705 14.634 132.975 ;
     RECT  0 133.245 14.634 133.515 ;
     RECT  0 133.785 14.634 134.055 ;
     RECT  0 134.325 14.634 134.595 ;
     RECT  0 134.865 14.634 135.135 ;
     RECT  0 135.405 14.634 135.675 ;
     RECT  0 135.945 14.634 136.215 ;
     RECT  0 136.485 14.634 136.755 ;
     RECT  0 137.025 14.634 137.295 ;
     RECT  0 137.565 14.634 137.835 ;
     RECT  0 138.105 14.634 138.375 ;
     RECT  0 138.645 14.634 138.915 ;
     RECT  0 139.185 14.634 139.455 ;
     RECT  0 139.725 14.634 139.995 ;
     RECT  0 140.265 14.634 140.535 ;
     RECT  0 140.805 14.634 141.075 ;
     RECT  0 141.345 14.634 141.615 ;
    LAYER RVTP ;
     RECT  0 0.675 14.634 0.945 ;
     RECT  0 1.215 14.634 1.485 ;
     RECT  0 1.755 14.634 2.025 ;
     RECT  0 2.295 14.634 2.565 ;
     RECT  0 2.835 14.634 3.105 ;
     RECT  0 3.375 14.634 3.645 ;
     RECT  0 3.915 14.634 4.185 ;
     RECT  0 4.455 14.634 4.725 ;
     RECT  0 4.995 14.634 5.265 ;
     RECT  0 5.535 14.634 5.805 ;
     RECT  0 6.075 14.634 6.345 ;
     RECT  0 6.615 14.634 6.885 ;
     RECT  0 7.155 14.634 7.425 ;
     RECT  0 7.695 14.634 7.965 ;
     RECT  0 8.235 14.634 8.505 ;
     RECT  0 8.775 14.634 9.045 ;
     RECT  0 9.315 14.634 9.585 ;
     RECT  0 9.855 14.634 10.125 ;
     RECT  0 10.395 14.634 10.665 ;
     RECT  0 10.935 14.634 11.205 ;
     RECT  0 11.475 14.634 11.745 ;
     RECT  0 12.015 14.634 12.285 ;
     RECT  0 12.555 14.634 12.825 ;
     RECT  0 13.095 14.634 13.365 ;
     RECT  0 13.635 14.634 13.905 ;
     RECT  0 14.175 14.634 14.445 ;
     RECT  0 14.715 14.634 14.985 ;
     RECT  0 15.255 14.634 15.525 ;
     RECT  0 15.795 14.634 16.065 ;
     RECT  0 16.335 14.634 16.605 ;
     RECT  0 16.875 14.634 17.145 ;
     RECT  0 17.415 14.634 17.685 ;
     RECT  0 17.955 14.634 18.225 ;
     RECT  0 18.495 14.634 18.765 ;
     RECT  0 19.035 14.634 19.305 ;
     RECT  0 19.575 14.634 19.845 ;
     RECT  0 20.115 14.634 20.385 ;
     RECT  0 20.655 14.634 20.925 ;
     RECT  0 21.195 14.634 21.465 ;
     RECT  0 21.735 14.634 22.005 ;
     RECT  0 22.275 14.634 22.545 ;
     RECT  0 22.815 14.634 23.085 ;
     RECT  0 23.355 14.634 23.625 ;
     RECT  0 23.895 14.634 24.165 ;
     RECT  0 24.435 14.634 24.705 ;
     RECT  0 24.975 14.634 25.245 ;
     RECT  0 25.515 14.634 25.785 ;
     RECT  0 26.055 14.634 26.325 ;
     RECT  0 26.595 14.634 26.865 ;
     RECT  0 27.135 14.634 27.405 ;
     RECT  0 27.675 14.634 27.945 ;
     RECT  0 28.215 14.634 28.485 ;
     RECT  0 28.755 14.634 29.025 ;
     RECT  0 29.295 14.634 29.565 ;
     RECT  0 29.835 14.634 30.105 ;
     RECT  0 30.375 14.634 30.645 ;
     RECT  0 30.915 14.634 31.185 ;
     RECT  0 31.455 14.634 31.725 ;
     RECT  0 31.995 14.634 32.265 ;
     RECT  0 32.535 14.634 32.805 ;
     RECT  0 33.075 14.634 33.345 ;
     RECT  0 33.615 14.634 33.885 ;
     RECT  0 34.155 14.634 34.425 ;
     RECT  0 34.695 14.634 34.965 ;
     RECT  0 35.235 14.634 35.505 ;
     RECT  0 35.775 14.634 36.045 ;
     RECT  0 36.315 14.634 36.585 ;
     RECT  0 36.855 14.634 37.125 ;
     RECT  0 37.395 14.634 37.665 ;
     RECT  0 37.935 14.634 38.205 ;
     RECT  0 38.475 14.634 38.745 ;
     RECT  0 39.015 14.634 39.285 ;
     RECT  0 39.555 14.634 39.825 ;
     RECT  0 40.095 14.634 40.365 ;
     RECT  0 40.635 14.634 40.905 ;
     RECT  0 41.175 14.634 41.445 ;
     RECT  0 41.715 14.634 41.985 ;
     RECT  0 42.255 14.634 42.525 ;
     RECT  0 42.795 14.634 43.065 ;
     RECT  0 43.335 14.634 43.605 ;
     RECT  0 43.875 14.634 44.145 ;
     RECT  0 44.415 14.634 44.685 ;
     RECT  0 44.955 14.634 45.225 ;
     RECT  0 45.495 14.634 45.765 ;
     RECT  0 46.035 14.634 46.305 ;
     RECT  0 46.575 14.634 46.845 ;
     RECT  0 47.115 14.634 47.385 ;
     RECT  0 47.655 14.634 47.925 ;
     RECT  0 48.195 14.634 48.465 ;
     RECT  0 48.735 14.634 49.005 ;
     RECT  0 49.275 14.634 49.545 ;
     RECT  0 49.815 14.634 50.085 ;
     RECT  0 50.355 14.634 50.625 ;
     RECT  0 50.895 14.634 51.165 ;
     RECT  0 51.435 14.634 51.705 ;
     RECT  0 51.975 14.634 52.245 ;
     RECT  0 52.515 14.634 52.785 ;
     RECT  0 53.055 14.634 53.325 ;
     RECT  0 53.595 14.634 53.865 ;
     RECT  0 54.135 14.634 54.405 ;
     RECT  0 54.675 14.634 54.945 ;
     RECT  0 55.215 14.634 55.485 ;
     RECT  0 55.755 14.634 56.025 ;
     RECT  0 56.295 14.634 56.565 ;
     RECT  0 56.835 14.634 57.105 ;
     RECT  0 57.375 14.634 57.645 ;
     RECT  0 57.915 14.634 58.185 ;
     RECT  0 58.455 14.634 58.725 ;
     RECT  0 58.995 14.634 59.265 ;
     RECT  0 59.535 14.634 59.805 ;
     RECT  0 60.075 14.634 60.345 ;
     RECT  0 60.615 14.634 60.885 ;
     RECT  0 61.155 14.634 61.425 ;
     RECT  0 61.695 14.634 61.965 ;
     RECT  0 62.235 14.634 62.505 ;
     RECT  0 62.775 14.634 63.045 ;
     RECT  0 63.315 14.634 63.585 ;
     RECT  0 63.855 14.634 64.125 ;
     RECT  0 64.395 14.634 64.665 ;
     RECT  0 64.935 14.634 65.205 ;
     RECT  0 65.475 14.634 65.745 ;
     RECT  0 66.015 14.634 66.285 ;
     RECT  0 66.555 14.634 66.825 ;
     RECT  0 67.095 14.634 67.365 ;
     RECT  0 67.635 14.634 67.905 ;
     RECT  0 68.175 14.634 68.445 ;
     RECT  0 68.715 14.634 68.985 ;
     RECT  0 69.255 14.634 69.525 ;
     RECT  0 69.795 14.634 70.065 ;
     RECT  0 70.335 14.634 70.605 ;
     RECT  0 70.875 14.634 71.145 ;
     RECT  0 71.415 14.634 71.685 ;
     RECT  0 71.955 14.634 72.225 ;
     RECT  0 72.495 14.634 72.765 ;
     RECT  0 73.035 14.634 73.305 ;
     RECT  0 73.575 14.634 73.845 ;
     RECT  0 74.115 14.634 74.385 ;
     RECT  0 74.655 14.634 74.925 ;
     RECT  0 75.195 14.634 75.465 ;
     RECT  0 75.735 14.634 76.005 ;
     RECT  0 76.275 14.634 76.545 ;
     RECT  0 76.815 14.634 77.085 ;
     RECT  0 77.355 14.634 77.625 ;
     RECT  0 77.895 14.634 78.165 ;
     RECT  0 78.435 14.634 78.705 ;
     RECT  0 78.975 14.634 79.245 ;
     RECT  0 79.515 14.634 79.785 ;
     RECT  0 80.055 14.634 80.325 ;
     RECT  0 80.595 14.634 80.865 ;
     RECT  0 81.135 14.634 81.405 ;
     RECT  0 81.675 14.634 81.945 ;
     RECT  0 82.215 14.634 82.485 ;
     RECT  0 82.755 14.634 83.025 ;
     RECT  0 83.295 14.634 83.565 ;
     RECT  0 83.835 14.634 84.105 ;
     RECT  0 84.375 14.634 84.645 ;
     RECT  0 84.915 14.634 85.185 ;
     RECT  0 85.455 14.634 85.725 ;
     RECT  0 85.995 14.634 86.265 ;
     RECT  0 86.535 14.634 86.805 ;
     RECT  0 87.075 14.634 87.345 ;
     RECT  0 87.615 14.634 87.885 ;
     RECT  0 88.155 14.634 88.425 ;
     RECT  0 88.695 14.634 88.965 ;
     RECT  0 89.235 14.634 89.505 ;
     RECT  0 89.775 14.634 90.045 ;
     RECT  0 90.315 14.634 90.585 ;
     RECT  0 90.855 14.634 91.125 ;
     RECT  0 91.395 14.634 91.665 ;
     RECT  0 91.935 14.634 92.205 ;
     RECT  0 92.475 14.634 92.745 ;
     RECT  0 93.015 14.634 93.285 ;
     RECT  0 93.555 14.634 93.825 ;
     RECT  0 94.095 14.634 94.365 ;
     RECT  0 94.635 14.634 94.905 ;
     RECT  0 95.175 14.634 95.445 ;
     RECT  0 95.715 14.634 95.985 ;
     RECT  0 96.255 14.634 96.525 ;
     RECT  0 96.795 14.634 97.065 ;
     RECT  0 97.335 14.634 97.605 ;
     RECT  0 97.875 14.634 98.145 ;
     RECT  0 98.415 14.634 98.685 ;
     RECT  0 98.955 14.634 99.225 ;
     RECT  0 99.495 14.634 99.765 ;
     RECT  0 100.035 14.634 100.305 ;
     RECT  0 100.575 14.634 100.845 ;
     RECT  0 101.115 14.634 101.385 ;
     RECT  0 101.655 14.634 101.925 ;
     RECT  0 102.195 14.634 102.465 ;
     RECT  0 102.735 14.634 103.005 ;
     RECT  0 103.275 14.634 103.545 ;
     RECT  0 103.815 14.634 104.085 ;
     RECT  0 104.355 14.634 104.625 ;
     RECT  0 104.895 14.634 105.165 ;
     RECT  0 105.435 14.634 105.705 ;
     RECT  0 105.975 14.634 106.245 ;
     RECT  0 106.515 14.634 106.785 ;
     RECT  0 107.055 14.634 107.325 ;
     RECT  0 107.595 14.634 107.865 ;
     RECT  0 108.135 14.634 108.405 ;
     RECT  0 108.675 14.634 108.945 ;
     RECT  0 109.215 14.634 109.485 ;
     RECT  0 109.755 14.634 110.025 ;
     RECT  0 110.295 14.634 110.565 ;
     RECT  0 110.835 14.634 111.105 ;
     RECT  0 111.375 14.634 111.645 ;
     RECT  0 111.915 14.634 112.185 ;
     RECT  0 112.455 14.634 112.725 ;
     RECT  0 112.995 14.634 113.265 ;
     RECT  0 113.535 14.634 113.805 ;
     RECT  0 114.075 14.634 114.345 ;
     RECT  0 114.615 14.634 114.885 ;
     RECT  0 115.155 14.634 115.425 ;
     RECT  0 115.695 14.634 115.965 ;
     RECT  0 116.235 14.634 116.505 ;
     RECT  0 116.775 14.634 117.045 ;
     RECT  0 117.315 14.634 117.585 ;
     RECT  0 117.855 14.634 118.125 ;
     RECT  0 118.395 14.634 118.665 ;
     RECT  0 118.935 14.634 119.205 ;
     RECT  0 119.475 14.634 119.745 ;
     RECT  0 120.015 14.634 120.285 ;
     RECT  0 120.555 14.634 120.825 ;
     RECT  0 121.095 14.634 121.365 ;
     RECT  0 121.635 14.634 121.905 ;
     RECT  0 122.175 14.634 122.445 ;
     RECT  0 122.715 14.634 122.985 ;
     RECT  0 123.255 14.634 123.525 ;
     RECT  0 123.795 14.634 124.065 ;
     RECT  0 124.335 14.634 124.605 ;
     RECT  0 124.875 14.634 125.145 ;
     RECT  0 125.415 14.634 125.685 ;
     RECT  0 125.955 14.634 126.225 ;
     RECT  0 126.495 14.634 126.765 ;
     RECT  0 127.035 14.634 127.305 ;
     RECT  0 127.575 14.634 127.845 ;
     RECT  0 128.115 14.634 128.385 ;
     RECT  0 128.655 14.634 128.925 ;
     RECT  0 129.195 14.634 129.465 ;
     RECT  0 129.735 14.634 130.005 ;
     RECT  0 130.275 14.634 130.545 ;
     RECT  0 130.815 14.634 131.085 ;
     RECT  0 131.355 14.634 131.625 ;
     RECT  0 131.895 14.634 132.165 ;
     RECT  0 132.435 14.634 132.705 ;
     RECT  0 132.975 14.634 133.245 ;
     RECT  0 133.515 14.634 133.785 ;
     RECT  0 134.055 14.634 134.325 ;
     RECT  0 134.595 14.634 134.865 ;
     RECT  0 135.135 14.634 135.405 ;
     RECT  0 135.675 14.634 135.945 ;
     RECT  0 136.215 14.634 136.485 ;
     RECT  0 136.755 14.634 137.025 ;
     RECT  0 137.295 14.634 137.565 ;
     RECT  0 137.835 14.634 138.105 ;
     RECT  0 138.375 14.634 138.645 ;
     RECT  0 138.915 14.634 139.185 ;
     RECT  0 139.455 14.634 139.725 ;
     RECT  0 139.995 14.634 140.265 ;
     RECT  0 140.535 14.634 140.805 ;
     RECT  0 141.075 14.634 141.345 ;
     RECT  0 141.615 14.634 141.75 ;
    LAYER M1 ;
     RECT  0 0.531 14.634 141.759 ;
    LAYER M2 ;
     RECT  0 0.531 14.634 141.759 ;
    LAYER M3 ;
     RECT  9.756 0.187 10.278 0.235 ;
     RECT  11.484 0.187 12.51 0.235 ;
     RECT  9.504 0.235 12.51 0.571 ;
     RECT  13.536 0.187 13.554 0.571 ;
     RECT  0.255 0.523 0.345 0.793 ;
     RECT  5.655 0.523 5.745 0.793 ;
     RECT  9.504 0.571 13.626 1.147 ;
     RECT  9.504 1.147 13.662 1.679 ;
     RECT  9.504 1.679 13.626 2.029 ;
     RECT  9.468 2.029 13.626 2.065 ;
     RECT  9.036 2.065 13.626 2.101 ;
     RECT  8.532 2.101 13.626 2.561 ;
     RECT  8.532 2.561 13.23 2.725 ;
     RECT  8.46 2.725 13.23 3.029 ;
     RECT  8.46 3.029 13.158 3.379 ;
     RECT  8.172 3.379 13.158 3.437 ;
     RECT  8.388 3.437 13.158 4.261 ;
     RECT  8.172 4.261 13.158 4.301 ;
     RECT  8.496 4.301 13.158 6.269 ;
     RECT  8.496 6.269 12.942 7.349 ;
     RECT  8.496 7.349 12.906 8.969 ;
     RECT  8.496 8.969 12.87 9.509 ;
     RECT  8.496 9.509 11.337 10.471 ;
     RECT  12.096 9.509 12.87 10.471 ;
     RECT  8.496 10.471 12.87 11.069 ;
     RECT  8.496 11.069 11.337 13.981 ;
     RECT  12.096 11.069 12.87 13.981 ;
     RECT  8.496 13.981 12.87 17.609 ;
     RECT  12.852 17.609 12.87 18.959 ;
     RECT  12.276 19.111 12.294 19.181 ;
     RECT  13.572 24.523 13.59 24.629 ;
     RECT  13.428 24.745 13.446 24.899 ;
     RECT  12.528 25.051 12.546 25.709 ;
     RECT  8.496 17.609 11.502 26.731 ;
     RECT  12.276 25.861 12.294 26.731 ;
     RECT  8.496 26.731 12.294 26.789 ;
     RECT  8.496 26.789 11.754 27.869 ;
     RECT  8.496 27.869 11.502 82.411 ;
     RECT  8.28 82.411 11.502 82.451 ;
     RECT  9 82.451 11.502 83.707 ;
     RECT  8.28 83.707 11.502 83.831 ;
     RECT  9 83.831 11.502 84.839 ;
     RECT  7.992 84.847 8.01 84.893 ;
     RECT  9.576 84.839 11.502 87.259 ;
     RECT  8.892 87.259 11.502 87.539 ;
     RECT  8.28 87.685 8.298 87.725 ;
     RECT  9.072 87.539 11.502 88.315 ;
     RECT  8.496 88.315 11.502 88.349 ;
     RECT  8.496 88.349 8.514 88.355 ;
     RECT  9.576 88.349 11.502 90.751 ;
     RECT  8.964 90.751 11.502 90.797 ;
     RECT  8.28 90.931 8.298 90.989 ;
     RECT  9.36 90.797 11.502 91.243 ;
     RECT  9.36 91.243 11.97 91.589 ;
     RECT  9.36 91.589 11.754 91.769 ;
     RECT  9.36 91.769 11.502 91.771 ;
     RECT  9.144 91.771 11.502 91.859 ;
     RECT  8.244 92.005 8.262 92.045 ;
     RECT  9.576 91.859 11.502 93.091 ;
     RECT  9.36 93.091 11.502 93.253 ;
     RECT  9.252 93.253 11.502 93.293 ;
     RECT  9.684 93.293 11.502 93.821 ;
     RECT  8.784 93.901 8.802 93.965 ;
     RECT  9.828 93.821 11.502 93.965 ;
     RECT  12.24 94.123 12.258 94.699 ;
     RECT  12.24 94.699 12.294 94.829 ;
     RECT  10.548 93.965 11.502 94.981 ;
     RECT  10.548 94.981 11.646 95.099 ;
     RECT  10.008 95.131 10.026 95.171 ;
     RECT  9.144 96.907 9.162 97.259 ;
     RECT  8.64 97.375 8.658 97.421 ;
     RECT  9.972 97.681 9.99 99.787 ;
     RECT  11.055 95.099 11.646 99.787 ;
     RECT  9.972 99.787 11.646 100.201 ;
     RECT  9.936 100.201 11.646 100.229 ;
     RECT  9.936 100.229 9.99 100.267 ;
     RECT  9.684 100.267 9.99 100.307 ;
     RECT  11.055 100.229 11.646 101.515 ;
     RECT  7.524 101.515 7.542 101.579 ;
     RECT  11.055 101.515 12.366 101.579 ;
     RECT  7.2 101.731 7.218 101.789 ;
     RECT  9.936 100.307 9.99 103.195 ;
     RECT  9.936 103.195 10.242 103.675 ;
     RECT  9.9 103.675 10.242 103.739 ;
     RECT  8.496 103.981 8.514 104.045 ;
     RECT  11.055 101.579 11.646 104.347 ;
     RECT  11.055 104.347 12.006 104.549 ;
     RECT  7.956 104.053 8.262 104.573 ;
     RECT  11.055 104.549 11.97 104.701 ;
     RECT  7.848 104.701 7.866 104.765 ;
     RECT  11.016 104.701 11.97 104.819 ;
     RECT  11.016 104.819 11.754 104.861 ;
     RECT  11.016 104.861 11.646 105.499 ;
     RECT  9.936 103.739 9.99 105.979 ;
     RECT  10.98 105.499 11.646 105.979 ;
     RECT  12.42 106.075 12.438 106.169 ;
     RECT  9.936 105.979 11.646 106.321 ;
     RECT  9.828 106.321 11.97 106.397 ;
     RECT  7.74 107.803 7.758 108.211 ;
     RECT  9.828 106.397 11.646 108.331 ;
     RECT  7.596 108.211 7.758 108.571 ;
     RECT  9.18 108.331 11.646 108.599 ;
     RECT  7.416 108.571 7.758 108.643 ;
     RECT  9.828 108.599 11.646 109.483 ;
     RECT  9.828 109.483 12.15 109.949 ;
     RECT  9.828 109.949 11.646 109.957 ;
     RECT  9.108 109.957 11.646 109.997 ;
     RECT  7.416 108.643 8.082 110.573 ;
     RECT  9.36 109.997 11.646 110.633 ;
     RECT  9.54 110.633 11.646 110.759 ;
     RECT  7.416 110.573 7.974 111.101 ;
     RECT  9.828 110.759 11.646 112.363 ;
     RECT  9.252 112.363 11.646 112.649 ;
     RECT  9.72 112.649 11.646 112.928 ;
     RECT  7.416 111.101 7.614 113.071 ;
     RECT  7.416 113.071 7.83 113.161 ;
     RECT  8.604 112.801 8.946 113.161 ;
     RECT  7.416 113.161 8.946 113.189 ;
     RECT  7.416 113.189 8.262 114.781 ;
     RECT  6.912 114.781 8.262 114.845 ;
     RECT  9.828 112.928 11.646 115.051 ;
     RECT  9.108 115.051 11.646 115.115 ;
     RECT  9.288 115.115 11.646 115.349 ;
     RECT  5.655 0.793 5.937 116.635 ;
     RECT  7.056 114.845 8.262 116.635 ;
     RECT  5.655 116.635 8.262 116.699 ;
     RECT  9.288 115.349 11.337 117.751 ;
     RECT  5.655 116.699 5.937 118.201 ;
     RECT  6.768 116.699 8.262 118.201 ;
     RECT  9 117.751 11.337 118.603 ;
     RECT  9 118.603 11.43 118.859 ;
     RECT  5.655 118.201 8.262 119.179 ;
     RECT  9 118.859 11.337 119.179 ;
     RECT  5.655 119.179 11.337 121.435 ;
     RECT  5.655 121.435 11.97 121.829 ;
     RECT  5.655 121.829 11.43 128.251 ;
     RECT  5.655 128.251 11.466 128.309 ;
     RECT  5.655 128.309 11.43 133.951 ;
     RECT  5.655 133.951 11.538 133.997 ;
     RECT  5.655 133.997 11.43 135.061 ;
     RECT  5.652 135.061 11.43 135.101 ;
     RECT  5.655 135.101 11.43 136.525 ;
     RECT  5.436 136.525 11.43 136.829 ;
     RECT  5.655 136.829 11.43 138.569 ;
     RECT  5.655 138.569 11.337 140.189 ;
     RECT  5.655 140.189 9.486 140.197 ;
     RECT  5.58 140.197 9.486 140.225 ;
     RECT  10.332 140.189 11.337 140.369 ;
     RECT  10.368 140.369 11.337 140.459 ;
     RECT  5.58 140.225 9.378 140.503 ;
     RECT  10.404 140.459 11.337 140.639 ;
     RECT  5.508 140.503 9.378 141.269 ;
     RECT  5.508 141.269 9.27 141.341 ;
     RECT  0.255 0.793 0.537 141.497 ;
     RECT  11.055 140.639 11.337 141.497 ;
     RECT  0.447 141.497 0.537 141.767 ;
     RECT  11.247 141.497 11.337 141.767 ;
     RECT  5.58 141.341 6.174 141.821 ;
     RECT  5.796 141.821 6.174 141.869 ;
     RECT  5.976 141.869 6.174 141.917 ;
     RECT  6.156 141.917 6.174 142.349 ;
    LAYER M4 ;
     RECT  0.248 0.528 0.352 141.492 ;
     RECT  0.352 0.798 0.44 141.492 ;
     RECT  0.44 0.798 0.544 141.762 ;
     RECT  5.269 140.832 5.453 140.856 ;
     RECT  5.453 140.832 5.509 141.336 ;
     RECT  5.641 135.072 5.648 135.096 ;
     RECT  5.173 136.8 5.648 136.824 ;
     RECT  5.365 139.2 5.648 139.224 ;
     RECT  5.509 140.208 5.648 142.248 ;
     RECT  5.648 0.528 5.752 142.248 ;
     RECT  5.752 0.798 5.944 142.248 ;
     RECT  5.944 141.312 6.037 142.248 ;
     RECT  6.037 141.312 6.185 142.344 ;
     RECT  5.944 119.184 6.275 119.208 ;
     RECT  5.944 129.984 6.689 130.056 ;
     RECT  6.689 129.984 6.761 130.008 ;
     RECT  5.944 132.48 6.761 132.504 ;
     RECT  5.944 134.544 6.797 135.096 ;
     RECT  6.797 134.544 6.803 134.712 ;
     RECT  6.185 141.312 6.803 142.248 ;
     RECT  5.944 116.64 6.851 116.664 ;
     RECT  5.944 136.224 6.869 136.248 ;
     RECT  5.944 121.536 6.913 121.56 ;
     RECT  7.081 118.032 7.165 118.056 ;
     RECT  5.944 140.112 7.189 140.232 ;
     RECT  7.141 101.76 7.229 101.784 ;
     RECT  7.189 118.608 7.273 118.632 ;
     RECT  7.244 128.016 7.331 128.04 ;
     RECT  7.189 140.064 7.381 140.232 ;
     RECT  7.513 101.52 7.597 101.544 ;
     RECT  7.381 139.632 7.625 140.232 ;
     RECT  6.803 141.312 7.649 141.336 ;
     RECT  7.621 131.568 7.705 131.592 ;
     RECT  7.628 113.088 7.715 113.112 ;
     RECT  7.429 111.072 7.717 111.096 ;
     RECT  7.649 141.264 7.732 141.336 ;
     RECT  7.685 107.808 7.769 107.832 ;
     RECT  6.803 134.544 7.769 134.568 ;
     RECT  7.717 110.496 7.804 111.096 ;
     RECT  5.944 114.816 7.877 114.84 ;
     RECT  7.813 104.736 7.9 104.76 ;
     RECT  7.837 121.44 7.955 121.464 ;
     RECT  7.868 129.12 7.955 129.144 ;
     RECT  7.804 110.544 7.985 111.096 ;
     RECT  7.861 133.968 7.985 133.992 ;
     RECT  7.957 84.864 8.044 84.888 ;
     RECT  7.429 124.752 8.053 124.776 ;
     RECT  7.985 110.544 8.093 110.568 ;
     RECT  7.732 141.216 8.149 141.336 ;
     RECT  8.156 120.768 8.243 120.792 ;
     RECT  7.829 116.304 8.281 116.328 ;
     RECT  8.204 92.016 8.291 92.04 ;
     RECT  8.053 124.752 8.305 125.592 ;
     RECT  7.909 104.064 8.317 104.568 ;
     RECT  8.245 82.416 8.332 82.44 ;
     RECT  8.252 90.96 8.339 90.984 ;
     RECT  8.269 127.728 8.353 127.752 ;
     RECT  8.305 124.752 8.413 125.64 ;
     RECT  8.149 3.408 8.428 4.296 ;
     RECT  8.149 141.216 8.435 142.248 ;
     RECT  8.428 3.408 8.437 3.768 ;
     RECT  7.957 87.696 8.444 87.72 ;
     RECT  8.413 124.32 8.483 125.64 ;
     RECT  8.389 131.04 8.489 131.064 ;
     RECT  7.625 140.064 8.513 140.232 ;
     RECT  8.435 141.216 8.513 141.336 ;
     RECT  8.437 2.736 8.524 3.768 ;
     RECT  8.444 87.696 8.531 88.344 ;
     RECT  8.341 138.192 8.561 138.216 ;
     RECT  8.485 104.016 8.569 104.04 ;
     RECT  8.485 132.048 8.572 132.072 ;
     RECT  8.513 140.064 8.597 141.336 ;
     RECT  8.483 124.32 8.627 125.592 ;
     RECT  8.581 97.392 8.669 97.416 ;
     RECT  8.665 119.184 8.771 119.208 ;
     RECT  8.725 113.088 8.812 113.112 ;
     RECT  8.732 93.936 8.819 93.96 ;
     RECT  8.531 87.696 8.837 87.864 ;
     RECT  8.524 3.408 8.86 3.768 ;
     RECT  8.809 131.568 8.893 131.592 ;
     RECT  8.725 128.928 8.917 128.952 ;
     RECT  8.837 87.264 8.921 87.864 ;
     RECT  8.053 135.648 8.921 135.672 ;
     RECT  8.725 137.376 8.953 137.4 ;
     RECT  8.86 3.648 8.963 3.768 ;
     RECT  8.876 4.848 8.963 4.872 ;
     RECT  8.917 128.88 9.001 128.952 ;
     RECT  8.924 133.104 9.011 133.128 ;
     RECT  8.627 124.32 9.025 124.728 ;
     RECT  8.953 90.768 9.037 90.792 ;
     RECT  9.068 109.968 9.109 109.992 ;
     RECT  8.252 83.712 9.145 83.736 ;
     RECT  8.921 87.84 9.145 87.864 ;
     RECT  9.061 115.056 9.148 115.08 ;
     RECT  9.109 109.968 9.155 110.616 ;
     RECT  9.089 96.912 9.173 96.936 ;
     RECT  8.597 141.264 9.173 141.336 ;
     RECT  9.109 11.904 9.196 11.928 ;
     RECT  9.116 8.352 9.203 8.376 ;
     RECT  9.133 91.776 9.251 91.8 ;
     RECT  9.169 120.288 9.253 120.312 ;
     RECT  8.597 140.064 9.281 140.232 ;
     RECT  9.173 141.312 9.281 141.336 ;
     RECT  9.241 112.368 9.325 112.92 ;
     RECT  9.301 129.696 9.388 129.72 ;
     RECT  9.301 91.488 9.389 91.512 ;
     RECT  9.155 110.496 9.389 110.616 ;
     RECT  9.397 12.192 9.484 12.216 ;
     RECT  8.953 136.944 9.497 137.4 ;
     RECT  9.281 140.064 9.497 140.184 ;
     RECT  9.5 117.648 9.587 117.672 ;
     RECT  9.389 110.496 9.613 110.52 ;
     RECT  8.963 3.648 9.628 3.672 ;
     RECT  9.169 108.336 9.683 108.36 ;
     RECT  9.493 0.24 9.701 0.264 ;
     RECT  9.637 13.632 9.721 13.656 ;
     RECT  9.644 83.664 9.731 83.688 ;
     RECT  9.644 100.272 9.731 100.296 ;
     RECT  9.061 93.168 9.788 93.816 ;
     RECT  9.701 0.192 9.817 0.264 ;
     RECT  9.74 12.912 9.827 13.08 ;
     RECT  9.025 123.744 9.836 124.728 ;
     RECT  9.788 93.168 9.865 93.96 ;
     RECT  9.865 93.936 9.875 93.96 ;
     RECT  9.836 123.744 9.875 124.824 ;
     RECT  9.875 124.8 9.923 124.824 ;
     RECT  9.829 132.816 9.929 132.84 ;
     RECT  9.497 140.064 9.929 140.136 ;
     RECT  9.877 103.68 9.964 103.704 ;
     RECT  9.932 80.304 10.019 80.328 ;
     RECT  9.325 112.896 10.019 112.92 ;
     RECT  9.98 95.136 10.067 95.16 ;
     RECT  9.997 123.696 10.081 123.72 ;
     RECT  9.817 0.192 10.105 0.6 ;
     RECT  9.745 9.552 10.261 9.576 ;
     RECT  9.497 136.944 10.316 136.968 ;
     RECT  9.827 12.912 10.597 12.936 ;
     RECT  10.105 114.864 10.597 114.888 ;
     RECT  10.261 106.656 10.681 106.68 ;
     RECT  10.453 118.848 10.709 118.872 ;
     RECT  10.597 110.496 10.825 110.52 ;
     RECT  10.213 91.248 10.844 91.272 ;
     RECT  10.261 9.552 10.885 9.672 ;
     RECT  10.681 106.08 10.925 106.68 ;
     RECT  10.825 110.496 10.925 110.952 ;
     RECT  10.172 130.224 10.925 130.248 ;
     RECT  10.925 105.504 10.933 106.68 ;
     RECT  10.925 110.256 10.933 110.952 ;
     RECT  10.105 0.192 11.048 1.176 ;
     RECT  10.717 4.224 11.048 4.248 ;
     RECT  10.933 8.496 11.048 8.52 ;
     RECT  10.885 9.552 11.048 10.248 ;
     RECT  10.597 12.432 11.048 12.936 ;
     RECT  10.741 16.416 11.048 16.44 ;
     RECT  10.825 28.848 11.048 28.872 ;
     RECT  10.645 67.776 11.048 67.8 ;
     RECT  10.028 84.768 11.048 84.792 ;
     RECT  10.453 87.696 11.048 87.72 ;
     RECT  10.844 90.432 11.048 91.272 ;
     RECT  10.741 94.992 11.048 95.016 ;
     RECT  10.645 99.792 11.048 99.816 ;
     RECT  10.213 103.2 11.048 103.224 ;
     RECT  10.933 104.832 11.048 106.68 ;
     RECT  10.933 109.968 11.048 110.952 ;
     RECT  10.597 114.864 11.048 115.416 ;
     RECT  10.421 117.456 11.048 117.48 ;
     RECT  10.709 118.608 11.048 118.872 ;
     RECT  9.709 120.192 11.048 120.216 ;
     RECT  10.861 124.32 11.048 124.344 ;
     RECT  10.597 125.616 11.048 125.64 ;
     RECT  10.925 127.152 11.048 127.176 ;
     RECT  10.46 128.448 11.048 128.472 ;
     RECT  10.925 130.032 11.048 130.248 ;
     RECT  10.556 133.968 11.048 133.992 ;
     RECT  10.316 136.368 11.048 136.968 ;
     RECT  9.929 140.064 11.048 140.088 ;
     RECT  11.048 0.192 11.24 141.492 ;
     RECT  11.24 0.192 11.344 141.762 ;
     RECT  11.344 109.488 11.369 109.992 ;
     RECT  11.344 94.128 11.485 94.776 ;
     RECT  11.344 118.608 11.485 118.632 ;
     RECT  11.344 128.256 11.521 128.28 ;
     RECT  11.344 4.224 11.548 4.296 ;
     RECT  11.344 101.52 11.548 101.784 ;
     RECT  11.344 133.968 11.593 133.992 ;
     RECT  11.344 10.512 11.788 11.064 ;
     RECT  11.344 91.248 11.788 91.752 ;
     RECT  11.344 104.352 11.788 104.856 ;
     RECT  11.788 91.248 11.981 91.272 ;
     RECT  11.788 104.352 11.981 104.472 ;
     RECT  11.344 106.368 11.981 106.392 ;
     RECT  11.344 6.816 11.987 7.272 ;
     RECT  11.344 16.992 11.989 17.592 ;
     RECT  11.344 121.44 12.025 121.464 ;
     RECT  11.981 104.352 12.061 104.376 ;
     RECT  11.344 26.736 12.083 27.384 ;
     RECT  11.344 9.072 12.097 9.096 ;
     RECT  12.083 26.736 12.124 26.76 ;
     RECT  11.989 17.136 12.205 17.592 ;
     RECT  11.369 109.488 12.205 109.512 ;
     RECT  11.485 94.128 12.313 94.728 ;
     RECT  11.344 19.152 12.316 19.176 ;
     RECT  12.313 94.704 12.349 94.728 ;
     RECT  11.548 101.52 12.377 101.544 ;
     RECT  12.325 11.376 12.413 11.4 ;
     RECT  11.548 4.224 12.421 4.248 ;
     RECT  12.409 106.08 12.493 106.104 ;
     RECT  12.421 3.84 12.508 4.248 ;
     RECT  12.205 17.136 12.515 17.544 ;
     RECT  12.469 7.392 12.556 7.416 ;
     RECT  12.515 17.52 12.556 17.544 ;
     RECT  12.509 4.56 12.593 4.584 ;
     RECT  11.344 0.192 12.613 1.704 ;
     RECT  11.344 2.784 12.851 2.856 ;
     RECT  12.851 2.784 13.043 2.808 ;
     RECT  12.613 0.192 13.426 1.752 ;
     RECT  13.426 0.192 13.537 1.8 ;
     RECT  13.561 2.304 13.645 2.328 ;
     RECT  13.561 24.528 13.645 24.552 ;
     RECT  13.537 0.192 13.717 1.176 ;
     RECT  13.717 0.192 13.811 0.6 ;
     RECT  13.811 0.192 13.907 0.216 ;
    LAYER M5 ;
     RECT  9.744 0.144 13.992 0.227 ;
     RECT  9.84 0.227 13.992 0.235 ;
     RECT  9.84 0.235 13.8 0.611 ;
     RECT  0.24 0.517 0.36 0.787 ;
     RECT  5.64 0.517 5.76 0.787 ;
     RECT  10.128 0.611 13.704 1.187 ;
     RECT  11.04 1.187 13.608 2.339 ;
     RECT  11.04 2.339 13.032 2.819 ;
     RECT  11.04 2.819 12.84 2.867 ;
     RECT  8.448 2.707 8.472 3.381 ;
     RECT  8.16 3.381 8.808 3.603 ;
     RECT  8.16 3.603 9.576 3.691 ;
     RECT  8.16 3.691 8.952 3.819 ;
     RECT  8.16 3.819 8.376 4.331 ;
     RECT  11.04 2.867 12.552 4.595 ;
     RECT  8.928 4.819 8.952 4.907 ;
     RECT  11.04 4.595 11.976 6.851 ;
     RECT  11.04 6.851 11.448 7.403 ;
     RECT  12.48 7.349 12.504 7.437 ;
     RECT  9.168 8.341 9.192 8.427 ;
     RECT  11.04 7.403 11.352 8.467 ;
     RECT  10.944 8.467 11.352 8.555 ;
     RECT  11.04 8.555 11.352 9.061 ;
     RECT  11.04 9.061 12.072 9.145 ;
     RECT  11.04 9.145 11.352 9.541 ;
     RECT  10.224 9.541 11.352 9.835 ;
     RECT  10.896 9.835 11.352 10.283 ;
     RECT  11.04 10.283 11.352 10.501 ;
     RECT  11.04 10.501 11.736 11.115 ;
     RECT  12.336 11.317 12.36 11.411 ;
     RECT  9.12 11.637 9.144 11.939 ;
     RECT  11.04 11.115 11.352 12.213 ;
     RECT  9.408 12.181 9.432 12.267 ;
     RECT  10.608 12.213 11.352 12.467 ;
     RECT  9.792 12.883 10.056 12.971 ;
     RECT  9.792 12.971 9.816 13.099 ;
     RECT  9.648 13.621 9.672 13.705 ;
     RECT  11.04 12.467 11.352 16.405 ;
     RECT  10.752 16.405 11.352 16.491 ;
     RECT  11.04 16.491 11.352 16.981 ;
     RECT  11.04 16.981 11.976 17.077 ;
     RECT  11.04 17.077 12.504 17.603 ;
     RECT  12.48 17.603 12.504 17.643 ;
     RECT  11.04 17.603 11.352 19.141 ;
     RECT  11.04 19.141 12.264 19.243 ;
     RECT  13.584 24.479 13.608 24.563 ;
     RECT  11.04 19.243 11.352 26.725 ;
     RECT  11.04 26.725 12.072 27.395 ;
     RECT  11.04 27.395 11.352 28.837 ;
     RECT  10.848 28.837 11.352 29.035 ;
     RECT  11.04 29.035 11.352 67.731 ;
     RECT  10.656 67.731 11.352 67.819 ;
     RECT  9.984 80.275 10.008 80.363 ;
     RECT  8.256 82.387 8.28 82.475 ;
     RECT  8.304 83.667 8.328 83.701 ;
     RECT  9.696 83.653 9.72 83.701 ;
     RECT  8.304 83.701 9.72 83.755 ;
     RECT  9.072 83.755 9.096 83.785 ;
     RECT  11.04 67.819 11.352 84.757 ;
     RECT  10.08 84.757 11.352 84.843 ;
     RECT  7.968 84.819 7.992 84.907 ;
     RECT  8.88 87.215 8.904 87.299 ;
     RECT  11.04 84.843 11.352 87.685 ;
     RECT  7.968 87.685 7.992 87.851 ;
     RECT  10.464 87.685 11.352 87.851 ;
     RECT  9.072 87.791 9.096 87.875 ;
     RECT  8.496 88.309 8.52 88.427 ;
     RECT  11.04 87.851 11.352 90.387 ;
     RECT  8.976 90.719 9 90.949 ;
     RECT  10.896 90.387 11.352 91.189 ;
     RECT  10.224 91.189 11.448 91.283 ;
     RECT  8.304 90.949 9 91.381 ;
     RECT  8.304 91.381 9.24 91.477 ;
     RECT  8.304 91.477 9.336 91.563 ;
     RECT  11.04 91.283 11.448 91.701 ;
     RECT  11.04 91.701 11.736 91.789 ;
     RECT  8.304 91.563 9.24 91.811 ;
     RECT  8.256 91.987 8.28 92.075 ;
     RECT  9.072 93.139 9.096 93.157 ;
     RECT  9.072 93.157 9.816 93.827 ;
     RECT  8.784 93.907 8.808 93.995 ;
     RECT  9.84 93.907 9.864 93.995 ;
     RECT  11.04 91.789 11.352 94.069 ;
     RECT  11.04 94.069 12.264 94.645 ;
     RECT  11.04 94.645 12.312 94.739 ;
     RECT  11.04 94.739 11.448 94.787 ;
     RECT  11.04 94.787 11.352 94.981 ;
     RECT  10.752 94.981 11.352 95.083 ;
     RECT  10.032 95.125 10.056 95.211 ;
     RECT  9.12 96.863 9.144 96.947 ;
     RECT  8.592 97.363 8.616 97.451 ;
     RECT  11.04 95.083 11.352 99.743 ;
     RECT  10.656 99.743 11.352 99.827 ;
     RECT  9.696 100.243 9.72 100.331 ;
     RECT  7.536 101.471 7.56 101.555 ;
     RECT  12.336 101.471 12.36 101.555 ;
     RECT  11.04 99.827 11.352 101.749 ;
     RECT  7.152 101.715 7.176 101.803 ;
     RECT  11.04 101.749 11.496 103.151 ;
     RECT  10.224 103.151 11.496 103.235 ;
     RECT  9.888 103.477 9.912 103.715 ;
     RECT  8.496 103.967 8.52 104.019 ;
     RECT  7.92 104.019 8.52 104.051 ;
     RECT  11.04 103.235 11.496 104.245 ;
     RECT  11.04 104.245 11.544 104.303 ;
     RECT  11.04 104.303 12.024 104.387 ;
     RECT  7.92 104.051 8.28 104.619 ;
     RECT  11.04 104.387 11.736 104.787 ;
     RECT  7.824 104.725 7.848 104.811 ;
     RECT  10.944 104.787 11.736 104.875 ;
     RECT  10.944 104.875 11.496 105.003 ;
     RECT  10.944 105.003 11.352 106.031 ;
     RECT  12.432 106.031 12.456 106.115 ;
     RECT  10.704 106.031 11.352 106.323 ;
     RECT  10.704 106.323 11.928 106.411 ;
     RECT  10.704 106.411 11.352 106.607 ;
     RECT  10.272 106.607 11.352 106.691 ;
     RECT  7.728 107.759 7.752 107.843 ;
     RECT  9.648 108.277 9.672 108.371 ;
     RECT  11.04 106.691 11.352 109.429 ;
     RECT  11.04 109.429 12.168 109.523 ;
     RECT  11.04 109.523 11.352 109.941 ;
     RECT  9.12 109.941 9.144 110.325 ;
     RECT  10.944 109.941 11.352 110.453 ;
     RECT  7.728 110.453 7.752 110.524 ;
     RECT  9.12 110.325 9.576 110.531 ;
     RECT  10.608 110.453 11.352 110.541 ;
     RECT  9.12 110.531 9.432 110.571 ;
     RECT  9.12 110.571 9.144 110.627 ;
     RECT  7.728 110.524 8.04 110.64 ;
     RECT  7.728 110.64 7.848 111.019 ;
     RECT  7.44 111.061 7.464 111.147 ;
     RECT  10.848 110.541 11.352 111.147 ;
     RECT  9.264 112.309 9.288 112.403 ;
     RECT  9.984 112.885 10.008 112.969 ;
     RECT  7.68 113.043 7.704 113.131 ;
     RECT  8.736 113.043 8.76 113.131 ;
     RECT  5.64 0.787 5.952 114.771 ;
     RECT  5.64 114.771 6.936 114.805 ;
     RECT  11.04 111.147 11.352 114.805 ;
     RECT  5.64 114.805 7.848 114.859 ;
     RECT  7.824 114.859 7.848 114.889 ;
     RECT  10.224 114.805 11.352 114.899 ;
     RECT  9.072 114.805 9.096 115.091 ;
     RECT  10.608 114.899 11.352 115.435 ;
     RECT  7.872 116.255 8.232 116.339 ;
     RECT  5.64 114.859 5.952 116.591 ;
     RECT  5.64 116.591 6.84 116.675 ;
     RECT  11.04 115.435 11.352 117.407 ;
     RECT  10.464 117.407 11.352 117.491 ;
     RECT  9.552 117.637 9.576 117.739 ;
     RECT  7.104 117.983 7.128 118.067 ;
     RECT  11.04 117.491 11.352 118.581 ;
     RECT  7.2 118.581 7.224 118.669 ;
     RECT  10.752 118.581 11.448 118.669 ;
     RECT  10.752 118.669 11.352 118.803 ;
     RECT  10.464 118.803 11.352 118.891 ;
     RECT  5.64 116.675 5.952 119.135 ;
     RECT  5.64 119.135 6.264 119.219 ;
     RECT  8.736 119.135 8.76 119.219 ;
     RECT  5.64 119.219 6.168 119.275 ;
     RECT  11.04 118.891 11.352 120.181 ;
     RECT  10.08 120.181 11.352 120.239 ;
     RECT  9.216 120.239 11.352 120.265 ;
     RECT  9.216 120.265 9.24 120.323 ;
     RECT  8.208 120.723 8.232 120.811 ;
     RECT  11.04 120.265 11.352 121.391 ;
     RECT  5.64 119.275 5.952 121.461 ;
     RECT  7.92 121.391 7.944 121.475 ;
     RECT  11.04 121.391 11.976 121.475 ;
     RECT  5.64 121.461 6.888 121.571 ;
     RECT  10.032 123.685 10.056 123.695 ;
     RECT  9.072 123.695 10.056 123.769 ;
     RECT  9.072 123.769 9.912 124.271 ;
     RECT  11.04 121.475 11.352 124.271 ;
     RECT  8.496 124.271 9.912 124.355 ;
     RECT  10.944 124.271 11.352 124.355 ;
     RECT  8.496 124.355 8.904 124.779 ;
     RECT  7.44 124.725 7.464 124.813 ;
     RECT  9.888 124.355 9.912 124.835 ;
     RECT  8.496 124.779 8.616 124.847 ;
     RECT  8.352 124.847 8.616 124.931 ;
     RECT  11.04 124.355 11.352 125.557 ;
     RECT  8.448 124.931 8.616 125.641 ;
     RECT  8.448 125.641 8.472 125.651 ;
     RECT  10.608 125.557 11.352 125.651 ;
     RECT  11.04 125.651 11.352 127.093 ;
     RECT  10.944 127.093 11.352 127.187 ;
     RECT  8.304 127.669 8.328 127.763 ;
     RECT  7.296 127.989 7.32 128.077 ;
     RECT  11.04 127.187 11.352 128.245 ;
     RECT  11.04 128.245 11.496 128.329 ;
     RECT  11.04 128.329 11.352 128.403 ;
     RECT  10.512 128.403 11.352 128.491 ;
     RECT  8.928 128.821 8.952 128.885 ;
     RECT  7.92 128.885 8.952 128.973 ;
     RECT  7.92 128.973 7.944 129.155 ;
     RECT  9.312 129.685 9.336 129.963 ;
     RECT  5.64 121.571 5.952 129.973 ;
     RECT  11.04 128.491 11.352 129.973 ;
     RECT  5.64 129.973 6.36 130.021 ;
     RECT  10.944 129.973 11.352 130.195 ;
     RECT  10.224 130.195 11.352 130.283 ;
     RECT  8.4 131.029 8.424 131.557 ;
     RECT  7.632 131.557 8.856 131.641 ;
     RECT  5.64 130.021 6.552 132.469 ;
     RECT  9.84 132.767 9.864 132.851 ;
     RECT  8.4 131.641 8.52 133.045 ;
     RECT  8.4 133.045 9 133.139 ;
     RECT  11.04 130.283 11.352 133.919 ;
     RECT  11.04 133.919 11.544 133.941 ;
     RECT  8.4 133.139 8.424 133.957 ;
     RECT  10.608 133.941 11.544 134.003 ;
     RECT  10.608 134.003 11.352 134.029 ;
     RECT  5.64 132.469 6.696 134.517 ;
     RECT  7.872 133.957 8.424 134.517 ;
     RECT  5.64 134.517 8.424 134.605 ;
     RECT  11.04 134.029 11.352 136.339 ;
     RECT  5.64 134.605 6.792 136.789 ;
     RECT  7.872 134.605 8.424 136.933 ;
     RECT  10.368 136.339 11.352 136.933 ;
     RECT  7.872 136.933 9 137.017 ;
     RECT  10.176 136.933 11.352 137.017 ;
     RECT  5.184 136.789 6.792 139.621 ;
     RECT  7.872 137.017 8.76 139.621 ;
     RECT  5.184 139.621 8.76 140.053 ;
     RECT  0.24 0.787 0.552 141.684 ;
     RECT  11.04 137.017 11.352 141.684 ;
     RECT  0.432 141.684 0.552 141.773 ;
     RECT  11.232 141.684 11.352 141.773 ;
     RECT  5.184 140.053 9.336 142.261 ;
     RECT  5.184 142.261 9.432 142.48 ;
    LAYER M6 ;
     RECT  0 119.796 6.133 120.66 ;
     RECT  6.133 119.232 6.229 120.66 ;
     RECT  6.229 119.168 6.837 120.66 ;
     RECT  0 125.196 6.837 126.06 ;
     RECT  0 108.996 6.901 109.86 ;
     RECT  6.837 119.168 6.91 121.504 ;
     RECT  6.805 116.608 6.955 116.64 ;
     RECT  6.91 119.168 7.093 121.44 ;
     RECT  7.093 118.016 7.162 121.44 ;
     RECT  6.773 101.76 7.187 101.792 ;
     RECT  7.162 118.592 7.275 121.44 ;
     RECT  6.901 108.996 7.475 111.136 ;
     RECT  0 0.996 7.541 1.86 ;
     RECT  7.093 3.968 7.541 4 ;
     RECT  7.525 101.504 7.595 101.536 ;
     RECT  0 130.596 7.598 131.46 ;
     RECT  0 103.596 7.605 104.46 ;
     RECT  0 114.396 7.669 115.26 ;
     RECT  7.475 108.996 7.717 111.008 ;
     RECT  6.757 134.528 7.763 134.56 ;
     RECT  7.717 107.776 7.787 111.008 ;
     RECT  7.605 103.596 7.859 104.8 ;
     RECT  7.541 0.996 7.861 4 ;
     RECT  7.669 113.088 7.861 115.26 ;
     RECT  7.285 128 7.909 128.032 ;
     RECT  7.275 119.796 7.979 121.44 ;
     RECT  7.221 84.864 8.003 84.896 ;
     RECT  7.787 108.996 8.043 111.008 ;
     RECT  8.043 108.996 8.062 110.624 ;
     RECT  7.861 113.088 8.243 116.32 ;
     RECT  0 92.796 8.245 93.66 ;
     RECT  0 81.996 8.293 82.86 ;
     RECT  8.245 92.032 8.293 93.66 ;
     RECT  7.909 128 8.293 128.928 ;
     RECT  7.979 119.796 8.299 120.8 ;
     RECT  7.859 103.596 8.314 104.608 ;
     RECT  8.293 127.68 8.363 128.928 ;
     RECT  0 98.196 8.437 99.06 ;
     RECT  7.861 0.996 8.483 4.32 ;
     RECT  0 87.396 8.485 88.26 ;
     RECT  6.837 124.736 8.485 126.06 ;
     RECT  7.598 130.596 8.485 131.616 ;
     RECT  8.485 87.396 8.555 88.416 ;
     RECT  0 141.396 8.629 141.684 ;
     RECT  8.299 119.796 8.725 120.66 ;
     RECT  8.293 91.008 8.773 93.66 ;
     RECT  8.243 113.088 8.811 115.26 ;
     RECT  8.725 119.168 8.811 120.66 ;
     RECT  8.483 3.392 8.819 4.32 ;
     RECT  8.555 87.396 8.869 88.26 ;
     RECT  8.485 130.596 8.89 132.064 ;
     RECT  8.819 3.648 8.917 4.32 ;
     RECT  8.869 87.232 8.939 88.26 ;
     RECT  8.773 91.008 8.942 93.984 ;
     RECT  0 135.996 8.942 136.86 ;
     RECT  8.363 128.832 8.949 128.928 ;
     RECT  8.89 130.596 8.949 131.46 ;
     RECT  8.917 3.648 9.003 4.896 ;
     RECT  8.949 128.832 9.003 131.46 ;
     RECT  8.942 90.752 9.011 93.984 ;
     RECT  0 11.796 9.013 12.66 ;
     RECT  8.949 132.8 9.022 133.088 ;
     RECT  8.485 124.288 9.061 126.06 ;
     RECT  0 6.396 9.141 7.26 ;
     RECT  9.013 11.648 9.155 12.66 ;
     RECT  8.437 96.896 9.155 99.06 ;
     RECT  9.155 11.796 9.205 12.66 ;
     RECT  9.141 6.396 9.214 8.416 ;
     RECT  9.205 11.796 9.269 12.96 ;
     RECT  9.253 112.32 9.323 112.928 ;
     RECT  9.011 91.2 9.347 93.984 ;
     RECT  9.003 129.92 9.347 131.46 ;
     RECT  8.062 108.996 9.397 110.496 ;
     RECT  8.629 141.396 9.443 142.304 ;
     RECT  8.811 114.396 9.525 115.26 ;
     RECT  9.003 3.648 9.587 3.68 ;
     RECT  9.269 11.796 9.637 13.024 ;
     RECT  9.397 108.996 9.637 110.56 ;
     RECT  9.155 98.196 9.685 99.06 ;
     RECT  9.637 11.796 9.771 13.664 ;
     RECT  8.314 103.596 9.781 104.46 ;
     RECT  9.771 11.796 9.835 13.088 ;
     RECT  9.022 132.8 9.875 132.832 ;
     RECT  9.347 92.796 9.899 93.984 ;
     RECT  9.954 80.32 10.027 80.352 ;
     RECT  9.323 112.896 10.042 112.928 ;
     RECT  9.835 11.796 10.067 12.96 ;
     RECT  8.293 81.996 10.069 83.744 ;
     RECT  10.021 95.04 10.091 95.2 ;
     RECT  9.061 123.712 10.091 126.06 ;
     RECT  10.069 81.996 10.155 84.832 ;
     RECT  0 17.196 10.165 18.06 ;
     RECT  9.781 103.488 10.213 104.46 ;
     RECT  10.213 9.792 10.229 9.824 ;
     RECT  8.942 135.996 10.234 136.992 ;
     RECT  10.213 103.168 10.283 104.46 ;
     RECT  9.637 108.288 10.293 110.56 ;
     RECT  10.165 106.624 10.307 106.656 ;
     RECT  10.229 9.664 10.347 9.824 ;
     RECT  9.525 117.696 10.421 117.728 ;
     RECT  10.421 117.44 10.453 117.728 ;
     RECT  8.811 119.796 10.453 120.66 ;
     RECT  0 27.996 10.485 28.86 ;
     RECT  10.453 117.44 10.499 120.66 ;
     RECT  9.685 98.196 10.539 100.32 ;
     RECT  0 65.796 10.613 66.66 ;
     RECT  9.525 114.396 10.643 115.424 ;
     RECT  10.501 128.448 10.667 128.48 ;
     RECT  9.214 6.396 10.677 7.26 ;
     RECT  10.613 65.796 10.691 67.808 ;
     RECT  10.539 98.196 10.691 99.808 ;
     RECT  10.165 16.448 10.787 18.06 ;
     RECT  10.091 95.04 10.787 95.072 ;
     RECT  10.155 81.996 10.859 83.744 ;
     RECT  10.293 108.288 10.859 111.136 ;
     RECT  9.347 91.2 10.869 91.232 ;
     RECT  10.485 27.996 10.883 29.024 ;
     RECT  10.859 108.996 10.883 111.136 ;
     RECT  10.741 10.24 10.931 10.272 ;
     RECT  10.677 6.396 10.933 7.392 ;
     RECT  10.283 103.596 10.933 104.46 ;
     RECT  10.67 106.048 10.933 106.4 ;
     RECT  10.091 124.288 10.933 126.06 ;
     RECT  9.347 130.24 10.933 131.46 ;
     RECT  10.869 90.432 10.942 91.232 ;
     RECT  10.883 108.996 11.051 110.176 ;
     RECT  10.933 129.984 11.179 131.46 ;
     RECT  10.933 6.396 11.243 8.544 ;
     RECT  10.933 124.288 11.243 127.136 ;
     RECT  10.067 11.796 11.253 12.66 ;
     RECT  9.899 92.796 11.253 93.66 ;
     RECT  11.051 108.996 11.307 109.984 ;
     RECT  8.483 0.996 11.352 1.86 ;
     RECT  11.253 10.56 11.352 12.66 ;
     RECT  10.787 17.024 11.352 18.06 ;
     RECT  0 22.596 11.352 23.46 ;
     RECT  10.883 27.996 11.352 28.86 ;
     RECT  0 33.396 11.352 34.26 ;
     RECT  0 38.796 11.352 39.66 ;
     RECT  0 44.196 11.352 45.06 ;
     RECT  0 49.596 11.352 50.46 ;
     RECT  0 54.996 11.352 55.86 ;
     RECT  0 60.396 11.352 61.26 ;
     RECT  10.691 65.796 11.352 66.66 ;
     RECT  0 71.196 11.352 72.06 ;
     RECT  0 76.596 11.352 77.46 ;
     RECT  10.859 81.996 11.352 82.86 ;
     RECT  8.939 87.396 11.352 88.26 ;
     RECT  10.691 98.196 11.352 99.06 ;
     RECT  11.307 108.996 11.352 109.86 ;
     RECT  10.643 114.396 11.352 115.26 ;
     RECT  10.499 118.592 11.352 120.66 ;
     RECT  11.243 124.288 11.352 126.06 ;
     RECT  11.179 130.596 11.352 131.46 ;
     RECT  10.234 135.996 11.352 136.86 ;
     RECT  11.352 124.288 11.371 125.484 ;
     RECT  10.942 91.2 11.381 91.232 ;
     RECT  11.253 92.796 11.381 94.752 ;
     RECT  11.381 91.2 11.459 94.752 ;
     RECT  11.352 118.592 11.459 120.084 ;
     RECT  10.997 4.288 11.507 4.32 ;
     RECT  11.438 128.256 11.507 128.288 ;
     RECT  10.597 133.952 11.578 133.984 ;
     RECT  11.352 10.56 11.747 12.084 ;
     RECT  11.459 91.712 11.747 94.688 ;
     RECT  10.933 103.596 11.747 106.4 ;
     RECT  11.747 106.048 11.939 106.4 ;
     RECT  11.352 0.996 11.944 1.568 ;
     RECT  11.243 6.396 11.944 7.392 ;
     RECT  11.747 11.328 11.944 12.084 ;
     RECT  11.352 22.596 11.944 22.884 ;
     RECT  11.352 27.996 11.944 28.284 ;
     RECT  11.352 33.396 11.944 33.684 ;
     RECT  11.352 38.796 11.944 39.084 ;
     RECT  11.352 44.196 11.944 44.484 ;
     RECT  11.352 49.596 11.944 49.884 ;
     RECT  11.352 54.996 11.944 55.284 ;
     RECT  11.352 60.396 11.944 60.684 ;
     RECT  11.352 65.796 11.944 66.084 ;
     RECT  11.352 71.196 11.944 71.484 ;
     RECT  11.352 76.596 11.944 76.884 ;
     RECT  11.352 81.996 11.944 82.284 ;
     RECT  11.352 87.396 11.944 87.684 ;
     RECT  11.747 92.796 11.944 94.688 ;
     RECT  11.352 98.196 11.944 98.484 ;
     RECT  11.747 103.596 11.944 104.352 ;
     RECT  11.352 108.996 11.944 109.472 ;
     RECT  11.352 114.396 11.944 114.684 ;
     RECT  11.459 119.796 11.944 120.084 ;
     RECT  11.371 125.196 11.944 125.484 ;
     RECT  11.352 130.596 11.944 130.884 ;
     RECT  11.352 135.996 11.944 136.284 ;
     RECT  9.443 141.396 11.944 141.684 ;
     RECT  11.944 104.32 12.035 104.352 ;
     RECT  11.941 121.408 12.075 121.44 ;
     RECT  12.014 9.088 12.083 9.12 ;
     RECT  11.944 109.44 12.203 109.472 ;
     RECT  11.944 94.08 12.275 94.688 ;
     RECT  12.213 19.2 12.286 19.232 ;
     RECT  12.275 94.656 12.346 94.688 ;
     RECT  11.944 11.328 12.371 11.36 ;
     RECT  11.352 17.024 12.395 17.632 ;
     RECT  12.325 101.504 12.395 101.536 ;
     RECT  11.939 106.048 12.467 106.08 ;
     RECT  12.405 3.84 12.478 3.872 ;
     RECT  11.944 7.36 12.515 7.392 ;
     RECT  12.395 17.088 12.515 17.632 ;
     RECT  11.944 1.536 12.523 1.568 ;
     RECT  12.515 17.088 12.538 17.12 ;
     RECT  13.55 24.512 13.619 24.544 ;
     RECT  13.557 0.192 14.003 0.224 ;
    LAYER M7 ;
     RECT  11.656 0.531 11.944 1.525 ;
     RECT  13.568 0.181 13.6 1.525 ;
     RECT  6.256 0.531 6.544 2.741 ;
     RECT  6.256 2.741 7.584 3.381 ;
     RECT  6.256 3.381 8.288 3.765 ;
     RECT  11.656 1.525 13.6 4.277 ;
     RECT  6.256 3.765 8.928 4.853 ;
     RECT  11.008 4.277 13.6 7.349 ;
     RECT  6.256 4.853 8.992 8.373 ;
     RECT  6.256 8.373 9.184 9.653 ;
     RECT  10.688 7.349 13.6 9.653 ;
     RECT  6.256 9.653 13.6 24.555 ;
     RECT  6.256 24.555 12.448 106.091 ;
     RECT  6.256 106.091 12.192 109.483 ;
     RECT  6.256 109.483 12.064 121.451 ;
     RECT  6.256 121.451 11.944 134.571 ;
     RECT  8.64 134.571 11.944 136.427 ;
     RECT  8.64 136.427 10.208 137.003 ;
     RECT  0.856 0.531 1.144 141.759 ;
     RECT  6.256 134.571 6.544 141.759 ;
     RECT  11.656 136.427 11.944 141.759 ;
     RECT  8.64 137.003 8.672 142.315 ;
  END
END hfd_stn_r3
END LIBRARY
